VERSION 5.8 ;
BUSBITCHARS "[]" ;
DIVIDERCHAR "/" ;
UNITS
    DATABASE MICRONS 1000 ;
END UNITS

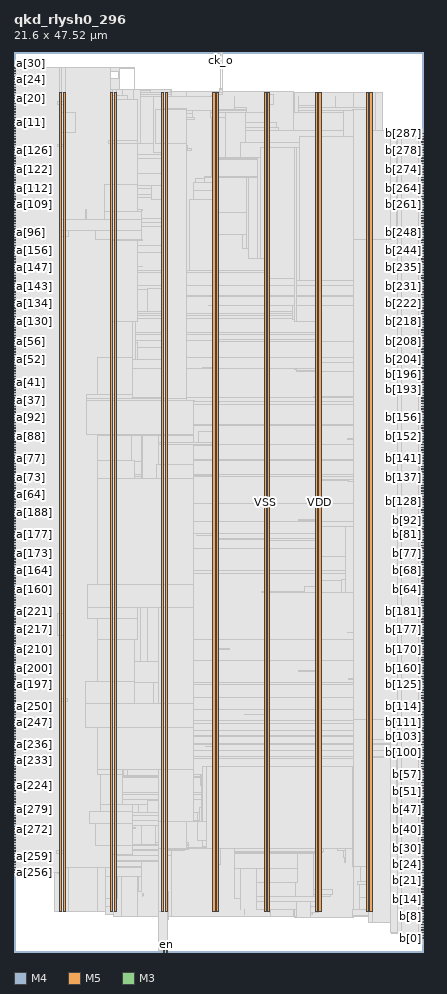
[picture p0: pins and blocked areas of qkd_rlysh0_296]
MACRO qkd_rlysh0_296
  FOREIGN qkd_rlysh0_296 0 0 ;
  CLASS BLOCK ;
  SIZE 21.6 BY 47.52 ;
  PIN a[0]
    DIRECTION INPUT ;
    USE SIGNAL ;
    PORT
      LAYER M4 ;
        RECT  0 42.192 0.084 42.216 ;
    END
  END a[0]
  PIN a[100]
    DIRECTION INPUT ;
    USE SIGNAL ;
    PORT
      LAYER M4 ;
        RECT  0 38.16 0.084 38.184 ;
    END
  END a[100]
  PIN a[101]
    DIRECTION INPUT ;
    USE SIGNAL ;
    PORT
      LAYER M4 ;
        RECT  0 38.304 0.084 38.328 ;
    END
  END a[101]
  PIN a[102]
    DIRECTION INPUT ;
    USE SIGNAL ;
    PORT
      LAYER M4 ;
        RECT  0 38.448 0.084 38.472 ;
    END
  END a[102]
  PIN a[103]
    DIRECTION INPUT ;
    USE SIGNAL ;
    PORT
      LAYER M4 ;
        RECT  0 38.592 0.084 38.616 ;
    END
  END a[103]
  PIN a[104]
    DIRECTION INPUT ;
    USE SIGNAL ;
    PORT
      LAYER M4 ;
        RECT  0 38.736 0.084 38.76 ;
    END
  END a[104]
  PIN a[105]
    DIRECTION INPUT ;
    USE SIGNAL ;
    PORT
      LAYER M4 ;
        RECT  0 38.88 0.084 38.904 ;
    END
  END a[105]
  PIN a[106]
    DIRECTION INPUT ;
    USE SIGNAL ;
    PORT
      LAYER M4 ;
        RECT  0 39.024 0.084 39.048 ;
    END
  END a[106]
  PIN a[107]
    DIRECTION INPUT ;
    USE SIGNAL ;
    PORT
      LAYER M4 ;
        RECT  0 39.168 0.084 39.192 ;
    END
  END a[107]
  PIN a[108]
    DIRECTION INPUT ;
    USE SIGNAL ;
    PORT
      LAYER M4 ;
        RECT  0 39.312 0.084 39.336 ;
    END
  END a[108]
  PIN a[109]
    DIRECTION INPUT ;
    USE SIGNAL ;
    PORT
      LAYER M4 ;
        RECT  0 39.456 0.084 39.48 ;
    END
  END a[109]
  PIN a[10]
    DIRECTION INPUT ;
    USE SIGNAL ;
    PORT
      LAYER M4 ;
        RECT  0 43.632 0.084 43.656 ;
    END
  END a[10]
  PIN a[110]
    DIRECTION INPUT ;
    USE SIGNAL ;
    PORT
      LAYER M4 ;
        RECT  0 39.6 0.084 39.624 ;
    END
  END a[110]
  PIN a[111]
    DIRECTION INPUT ;
    USE SIGNAL ;
    PORT
      LAYER M4 ;
        RECT  0 39.744 0.084 39.768 ;
    END
  END a[111]
  PIN a[112]
    DIRECTION INPUT ;
    USE SIGNAL ;
    PORT
      LAYER M4 ;
        RECT  0 39.888 0.084 39.912 ;
    END
  END a[112]
  PIN a[113]
    DIRECTION INPUT ;
    USE SIGNAL ;
    PORT
      LAYER M4 ;
        RECT  0 40.032 0.084 40.056 ;
    END
  END a[113]
  PIN a[114]
    DIRECTION INPUT ;
    USE SIGNAL ;
    PORT
      LAYER M4 ;
        RECT  0 40.176 0.084 40.2 ;
    END
  END a[114]
  PIN a[115]
    DIRECTION INPUT ;
    USE SIGNAL ;
    PORT
      LAYER M4 ;
        RECT  0 40.32 0.084 40.344 ;
    END
  END a[115]
  PIN a[116]
    DIRECTION INPUT ;
    USE SIGNAL ;
    PORT
      LAYER M4 ;
        RECT  0 40.464 0.084 40.488 ;
    END
  END a[116]
  PIN a[117]
    DIRECTION INPUT ;
    USE SIGNAL ;
    PORT
      LAYER M4 ;
        RECT  0 40.608 0.084 40.632 ;
    END
  END a[117]
  PIN a[118]
    DIRECTION INPUT ;
    USE SIGNAL ;
    PORT
      LAYER M4 ;
        RECT  0 40.752 0.084 40.776 ;
    END
  END a[118]
  PIN a[119]
    DIRECTION INPUT ;
    USE SIGNAL ;
    PORT
      LAYER M4 ;
        RECT  0 40.896 0.084 40.92 ;
    END
  END a[119]
  PIN a[11]
    DIRECTION INPUT ;
    USE SIGNAL ;
    PORT
      LAYER M4 ;
        RECT  0 43.776 0.084 43.8 ;
    END
  END a[11]
  PIN a[120]
    DIRECTION INPUT ;
    USE SIGNAL ;
    PORT
      LAYER M4 ;
        RECT  0 41.04 0.084 41.064 ;
    END
  END a[120]
  PIN a[121]
    DIRECTION INPUT ;
    USE SIGNAL ;
    PORT
      LAYER M4 ;
        RECT  0 41.184 0.084 41.208 ;
    END
  END a[121]
  PIN a[122]
    DIRECTION INPUT ;
    USE SIGNAL ;
    PORT
      LAYER M4 ;
        RECT  0 41.328 0.084 41.352 ;
    END
  END a[122]
  PIN a[123]
    DIRECTION INPUT ;
    USE SIGNAL ;
    PORT
      LAYER M4 ;
        RECT  0 41.472 0.084 41.496 ;
    END
  END a[123]
  PIN a[124]
    DIRECTION INPUT ;
    USE SIGNAL ;
    PORT
      LAYER M4 ;
        RECT  0 41.616 0.084 41.64 ;
    END
  END a[124]
  PIN a[125]
    DIRECTION INPUT ;
    USE SIGNAL ;
    PORT
      LAYER M4 ;
        RECT  0 41.76 0.084 41.784 ;
    END
  END a[125]
  PIN a[126]
    DIRECTION INPUT ;
    USE SIGNAL ;
    PORT
      LAYER M4 ;
        RECT  0 41.904 0.084 41.928 ;
    END
  END a[126]
  PIN a[127]
    DIRECTION INPUT ;
    USE SIGNAL ;
    PORT
      LAYER M4 ;
        RECT  0 42.048 0.084 42.072 ;
    END
  END a[127]
  PIN a[128]
    DIRECTION INPUT ;
    USE SIGNAL ;
    PORT
      LAYER M4 ;
        RECT  0 32.976 0.084 33 ;
    END
  END a[128]
  PIN a[129]
    DIRECTION INPUT ;
    USE SIGNAL ;
    PORT
      LAYER M4 ;
        RECT  0 33.12 0.084 33.144 ;
    END
  END a[129]
  PIN a[12]
    DIRECTION INPUT ;
    USE SIGNAL ;
    PORT
      LAYER M4 ;
        RECT  0 43.92 0.084 43.944 ;
    END
  END a[12]
  PIN a[130]
    DIRECTION INPUT ;
    USE SIGNAL ;
    PORT
      LAYER M4 ;
        RECT  0 33.264 0.084 33.288 ;
    END
  END a[130]
  PIN a[131]
    DIRECTION INPUT ;
    USE SIGNAL ;
    PORT
      LAYER M4 ;
        RECT  0 33.408 0.084 33.432 ;
    END
  END a[131]
  PIN a[132]
    DIRECTION INPUT ;
    USE SIGNAL ;
    PORT
      LAYER M4 ;
        RECT  0 33.552 0.084 33.576 ;
    END
  END a[132]
  PIN a[133]
    DIRECTION INPUT ;
    USE SIGNAL ;
    PORT
      LAYER M4 ;
        RECT  0 33.696 0.084 33.72 ;
    END
  END a[133]
  PIN a[134]
    DIRECTION INPUT ;
    USE SIGNAL ;
    PORT
      LAYER M4 ;
        RECT  0 33.84 0.084 33.864 ;
    END
  END a[134]
  PIN a[135]
    DIRECTION INPUT ;
    USE SIGNAL ;
    PORT
      LAYER M4 ;
        RECT  0 33.984 0.084 34.008 ;
    END
  END a[135]
  PIN a[136]
    DIRECTION INPUT ;
    USE SIGNAL ;
    PORT
      LAYER M4 ;
        RECT  0 34.128 0.084 34.152 ;
    END
  END a[136]
  PIN a[137]
    DIRECTION INPUT ;
    USE SIGNAL ;
    PORT
      LAYER M4 ;
        RECT  0 34.272 0.084 34.296 ;
    END
  END a[137]
  PIN a[138]
    DIRECTION INPUT ;
    USE SIGNAL ;
    PORT
      LAYER M4 ;
        RECT  0 34.416 0.084 34.44 ;
    END
  END a[138]
  PIN a[139]
    DIRECTION INPUT ;
    USE SIGNAL ;
    PORT
      LAYER M4 ;
        RECT  0 34.56 0.084 34.584 ;
    END
  END a[139]
  PIN a[13]
    DIRECTION INPUT ;
    USE SIGNAL ;
    PORT
      LAYER M4 ;
        RECT  0 44.064 0.084 44.088 ;
    END
  END a[13]
  PIN a[140]
    DIRECTION INPUT ;
    USE SIGNAL ;
    PORT
      LAYER M4 ;
        RECT  0 34.704 0.084 34.728 ;
    END
  END a[140]
  PIN a[141]
    DIRECTION INPUT ;
    USE SIGNAL ;
    PORT
      LAYER M4 ;
        RECT  0 34.848 0.084 34.872 ;
    END
  END a[141]
  PIN a[142]
    DIRECTION INPUT ;
    USE SIGNAL ;
    PORT
      LAYER M4 ;
        RECT  0 34.992 0.084 35.016 ;
    END
  END a[142]
  PIN a[143]
    DIRECTION INPUT ;
    USE SIGNAL ;
    PORT
      LAYER M4 ;
        RECT  0 35.136 0.084 35.16 ;
    END
  END a[143]
  PIN a[144]
    DIRECTION INPUT ;
    USE SIGNAL ;
    PORT
      LAYER M4 ;
        RECT  0 35.28 0.084 35.304 ;
    END
  END a[144]
  PIN a[145]
    DIRECTION INPUT ;
    USE SIGNAL ;
    PORT
      LAYER M4 ;
        RECT  0 35.424 0.084 35.448 ;
    END
  END a[145]
  PIN a[146]
    DIRECTION INPUT ;
    USE SIGNAL ;
    PORT
      LAYER M4 ;
        RECT  0 35.568 0.084 35.592 ;
    END
  END a[146]
  PIN a[147]
    DIRECTION INPUT ;
    USE SIGNAL ;
    PORT
      LAYER M4 ;
        RECT  0 35.712 0.084 35.736 ;
    END
  END a[147]
  PIN a[148]
    DIRECTION INPUT ;
    USE SIGNAL ;
    PORT
      LAYER M4 ;
        RECT  0 35.856 0.084 35.88 ;
    END
  END a[148]
  PIN a[149]
    DIRECTION INPUT ;
    USE SIGNAL ;
    PORT
      LAYER M4 ;
        RECT  0 36 0.084 36.024 ;
    END
  END a[149]
  PIN a[14]
    DIRECTION INPUT ;
    USE SIGNAL ;
    PORT
      LAYER M4 ;
        RECT  0 44.208 0.084 44.232 ;
    END
  END a[14]
  PIN a[150]
    DIRECTION INPUT ;
    USE SIGNAL ;
    PORT
      LAYER M4 ;
        RECT  0 36.144 0.084 36.168 ;
    END
  END a[150]
  PIN a[151]
    DIRECTION INPUT ;
    USE SIGNAL ;
    PORT
      LAYER M4 ;
        RECT  0 36.288 0.084 36.312 ;
    END
  END a[151]
  PIN a[152]
    DIRECTION INPUT ;
    USE SIGNAL ;
    PORT
      LAYER M4 ;
        RECT  0 36.432 0.084 36.456 ;
    END
  END a[152]
  PIN a[153]
    DIRECTION INPUT ;
    USE SIGNAL ;
    PORT
      LAYER M4 ;
        RECT  0 36.576 0.084 36.6 ;
    END
  END a[153]
  PIN a[154]
    DIRECTION INPUT ;
    USE SIGNAL ;
    PORT
      LAYER M4 ;
        RECT  0 36.72 0.084 36.744 ;
    END
  END a[154]
  PIN a[155]
    DIRECTION INPUT ;
    USE SIGNAL ;
    PORT
      LAYER M4 ;
        RECT  0 36.864 0.084 36.888 ;
    END
  END a[155]
  PIN a[156]
    DIRECTION INPUT ;
    USE SIGNAL ;
    PORT
      LAYER M4 ;
        RECT  0 37.008 0.084 37.032 ;
    END
  END a[156]
  PIN a[157]
    DIRECTION INPUT ;
    USE SIGNAL ;
    PORT
      LAYER M4 ;
        RECT  0 37.152 0.084 37.176 ;
    END
  END a[157]
  PIN a[158]
    DIRECTION INPUT ;
    USE SIGNAL ;
    PORT
      LAYER M4 ;
        RECT  0 37.296 0.084 37.32 ;
    END
  END a[158]
  PIN a[159]
    DIRECTION INPUT ;
    USE SIGNAL ;
    PORT
      LAYER M4 ;
        RECT  0 37.44 0.084 37.464 ;
    END
  END a[159]
  PIN a[15]
    DIRECTION INPUT ;
    USE SIGNAL ;
    PORT
      LAYER M4 ;
        RECT  0 44.352 0.084 44.376 ;
    END
  END a[15]
  PIN a[160]
    DIRECTION INPUT ;
    USE SIGNAL ;
    PORT
      LAYER M4 ;
        RECT  0 19.152 0.084 19.176 ;
    END
  END a[160]
  PIN a[161]
    DIRECTION INPUT ;
    USE SIGNAL ;
    PORT
      LAYER M4 ;
        RECT  0 19.296 0.084 19.32 ;
    END
  END a[161]
  PIN a[162]
    DIRECTION INPUT ;
    USE SIGNAL ;
    PORT
      LAYER M4 ;
        RECT  0 19.44 0.084 19.464 ;
    END
  END a[162]
  PIN a[163]
    DIRECTION INPUT ;
    USE SIGNAL ;
    PORT
      LAYER M4 ;
        RECT  0 19.584 0.084 19.608 ;
    END
  END a[163]
  PIN a[164]
    DIRECTION INPUT ;
    USE SIGNAL ;
    PORT
      LAYER M4 ;
        RECT  0 19.728 0.084 19.752 ;
    END
  END a[164]
  PIN a[165]
    DIRECTION INPUT ;
    USE SIGNAL ;
    PORT
      LAYER M4 ;
        RECT  0 19.872 0.084 19.896 ;
    END
  END a[165]
  PIN a[166]
    DIRECTION INPUT ;
    USE SIGNAL ;
    PORT
      LAYER M4 ;
        RECT  0 20.016 0.084 20.04 ;
    END
  END a[166]
  PIN a[167]
    DIRECTION INPUT ;
    USE SIGNAL ;
    PORT
      LAYER M4 ;
        RECT  0 20.16 0.084 20.184 ;
    END
  END a[167]
  PIN a[168]
    DIRECTION INPUT ;
    USE SIGNAL ;
    PORT
      LAYER M4 ;
        RECT  0 20.304 0.084 20.328 ;
    END
  END a[168]
  PIN a[169]
    DIRECTION INPUT ;
    USE SIGNAL ;
    PORT
      LAYER M4 ;
        RECT  0 20.448 0.084 20.472 ;
    END
  END a[169]
  PIN a[16]
    DIRECTION INPUT ;
    USE SIGNAL ;
    PORT
      LAYER M4 ;
        RECT  0 44.496 0.084 44.52 ;
    END
  END a[16]
  PIN a[170]
    DIRECTION INPUT ;
    USE SIGNAL ;
    PORT
      LAYER M4 ;
        RECT  0 20.592 0.084 20.616 ;
    END
  END a[170]
  PIN a[171]
    DIRECTION INPUT ;
    USE SIGNAL ;
    PORT
      LAYER M4 ;
        RECT  0 20.736 0.084 20.76 ;
    END
  END a[171]
  PIN a[172]
    DIRECTION INPUT ;
    USE SIGNAL ;
    PORT
      LAYER M4 ;
        RECT  0 20.88 0.084 20.904 ;
    END
  END a[172]
  PIN a[173]
    DIRECTION INPUT ;
    USE SIGNAL ;
    PORT
      LAYER M4 ;
        RECT  0 21.024 0.084 21.048 ;
    END
  END a[173]
  PIN a[174]
    DIRECTION INPUT ;
    USE SIGNAL ;
    PORT
      LAYER M4 ;
        RECT  0 21.168 0.084 21.192 ;
    END
  END a[174]
  PIN a[175]
    DIRECTION INPUT ;
    USE SIGNAL ;
    PORT
      LAYER M4 ;
        RECT  0 21.312 0.084 21.336 ;
    END
  END a[175]
  PIN a[176]
    DIRECTION INPUT ;
    USE SIGNAL ;
    PORT
      LAYER M4 ;
        RECT  0 21.456 0.084 21.48 ;
    END
  END a[176]
  PIN a[177]
    DIRECTION INPUT ;
    USE SIGNAL ;
    PORT
      LAYER M4 ;
        RECT  0 21.6 0.084 21.624 ;
    END
  END a[177]
  PIN a[178]
    DIRECTION INPUT ;
    USE SIGNAL ;
    PORT
      LAYER M4 ;
        RECT  0 21.744 0.084 21.768 ;
    END
  END a[178]
  PIN a[179]
    DIRECTION INPUT ;
    USE SIGNAL ;
    PORT
      LAYER M4 ;
        RECT  0 21.888 0.084 21.912 ;
    END
  END a[179]
  PIN a[17]
    DIRECTION INPUT ;
    USE SIGNAL ;
    PORT
      LAYER M4 ;
        RECT  0 44.64 0.084 44.664 ;
    END
  END a[17]
  PIN a[180]
    DIRECTION INPUT ;
    USE SIGNAL ;
    PORT
      LAYER M4 ;
        RECT  0 22.032 0.084 22.056 ;
    END
  END a[180]
  PIN a[181]
    DIRECTION INPUT ;
    USE SIGNAL ;
    PORT
      LAYER M4 ;
        RECT  0 22.176 0.084 22.2 ;
    END
  END a[181]
  PIN a[182]
    DIRECTION INPUT ;
    USE SIGNAL ;
    PORT
      LAYER M4 ;
        RECT  0 22.32 0.084 22.344 ;
    END
  END a[182]
  PIN a[183]
    DIRECTION INPUT ;
    USE SIGNAL ;
    PORT
      LAYER M4 ;
        RECT  0 22.464 0.084 22.488 ;
    END
  END a[183]
  PIN a[184]
    DIRECTION INPUT ;
    USE SIGNAL ;
    PORT
      LAYER M4 ;
        RECT  0 22.608 0.084 22.632 ;
    END
  END a[184]
  PIN a[185]
    DIRECTION INPUT ;
    USE SIGNAL ;
    PORT
      LAYER M4 ;
        RECT  0 22.752 0.084 22.776 ;
    END
  END a[185]
  PIN a[186]
    DIRECTION INPUT ;
    USE SIGNAL ;
    PORT
      LAYER M4 ;
        RECT  0 22.896 0.084 22.92 ;
    END
  END a[186]
  PIN a[187]
    DIRECTION INPUT ;
    USE SIGNAL ;
    PORT
      LAYER M4 ;
        RECT  0 23.04 0.084 23.064 ;
    END
  END a[187]
  PIN a[188]
    DIRECTION INPUT ;
    USE SIGNAL ;
    PORT
      LAYER M4 ;
        RECT  0 23.184 0.084 23.208 ;
    END
  END a[188]
  PIN a[189]
    DIRECTION INPUT ;
    USE SIGNAL ;
    PORT
      LAYER M4 ;
        RECT  0 23.328 0.084 23.352 ;
    END
  END a[189]
  PIN a[18]
    DIRECTION INPUT ;
    USE SIGNAL ;
    PORT
      LAYER M4 ;
        RECT  0 44.784 0.084 44.808 ;
    END
  END a[18]
  PIN a[190]
    DIRECTION INPUT ;
    USE SIGNAL ;
    PORT
      LAYER M4 ;
        RECT  0 23.472 0.084 23.496 ;
    END
  END a[190]
  PIN a[191]
    DIRECTION INPUT ;
    USE SIGNAL ;
    PORT
      LAYER M4 ;
        RECT  0 23.616 0.084 23.64 ;
    END
  END a[191]
  PIN a[192]
    DIRECTION INPUT ;
    USE SIGNAL ;
    PORT
      LAYER M4 ;
        RECT  0 13.392 0.084 13.416 ;
    END
  END a[192]
  PIN a[193]
    DIRECTION INPUT ;
    USE SIGNAL ;
    PORT
      LAYER M4 ;
        RECT  0 13.536 0.084 13.56 ;
    END
  END a[193]
  PIN a[194]
    DIRECTION INPUT ;
    USE SIGNAL ;
    PORT
      LAYER M4 ;
        RECT  0 13.68 0.084 13.704 ;
    END
  END a[194]
  PIN a[195]
    DIRECTION INPUT ;
    USE SIGNAL ;
    PORT
      LAYER M4 ;
        RECT  0 13.824 0.084 13.848 ;
    END
  END a[195]
  PIN a[196]
    DIRECTION INPUT ;
    USE SIGNAL ;
    PORT
      LAYER M4 ;
        RECT  0 13.968 0.084 13.992 ;
    END
  END a[196]
  PIN a[197]
    DIRECTION INPUT ;
    USE SIGNAL ;
    PORT
      LAYER M4 ;
        RECT  0 14.112 0.084 14.136 ;
    END
  END a[197]
  PIN a[198]
    DIRECTION INPUT ;
    USE SIGNAL ;
    PORT
      LAYER M4 ;
        RECT  0 14.256 0.084 14.28 ;
    END
  END a[198]
  PIN a[199]
    DIRECTION INPUT ;
    USE SIGNAL ;
    PORT
      LAYER M4 ;
        RECT  0 14.4 0.084 14.424 ;
    END
  END a[199]
  PIN a[19]
    DIRECTION INPUT ;
    USE SIGNAL ;
    PORT
      LAYER M4 ;
        RECT  0 44.928 0.084 44.952 ;
    END
  END a[19]
  PIN a[1]
    DIRECTION INPUT ;
    USE SIGNAL ;
    PORT
      LAYER M4 ;
        RECT  0 42.336 0.084 42.36 ;
    END
  END a[1]
  PIN a[200]
    DIRECTION INPUT ;
    USE SIGNAL ;
    PORT
      LAYER M4 ;
        RECT  0 14.544 0.084 14.568 ;
    END
  END a[200]
  PIN a[201]
    DIRECTION INPUT ;
    USE SIGNAL ;
    PORT
      LAYER M4 ;
        RECT  0 14.688 0.084 14.712 ;
    END
  END a[201]
  PIN a[202]
    DIRECTION INPUT ;
    USE SIGNAL ;
    PORT
      LAYER M4 ;
        RECT  0 14.832 0.084 14.856 ;
    END
  END a[202]
  PIN a[203]
    DIRECTION INPUT ;
    USE SIGNAL ;
    PORT
      LAYER M4 ;
        RECT  0 14.976 0.084 15 ;
    END
  END a[203]
  PIN a[204]
    DIRECTION INPUT ;
    USE SIGNAL ;
    PORT
      LAYER M4 ;
        RECT  0 15.12 0.084 15.144 ;
    END
  END a[204]
  PIN a[205]
    DIRECTION INPUT ;
    USE SIGNAL ;
    PORT
      LAYER M4 ;
        RECT  0 15.264 0.084 15.288 ;
    END
  END a[205]
  PIN a[206]
    DIRECTION INPUT ;
    USE SIGNAL ;
    PORT
      LAYER M4 ;
        RECT  0 15.408 0.084 15.432 ;
    END
  END a[206]
  PIN a[207]
    DIRECTION INPUT ;
    USE SIGNAL ;
    PORT
      LAYER M4 ;
        RECT  0 15.552 0.084 15.576 ;
    END
  END a[207]
  PIN a[208]
    DIRECTION INPUT ;
    USE SIGNAL ;
    PORT
      LAYER M4 ;
        RECT  0 15.696 0.084 15.72 ;
    END
  END a[208]
  PIN a[209]
    DIRECTION INPUT ;
    USE SIGNAL ;
    PORT
      LAYER M4 ;
        RECT  0 15.84 0.084 15.864 ;
    END
  END a[209]
  PIN a[20]
    DIRECTION INPUT ;
    USE SIGNAL ;
    PORT
      LAYER M4 ;
        RECT  0 45.072 0.084 45.096 ;
    END
  END a[20]
  PIN a[210]
    DIRECTION INPUT ;
    USE SIGNAL ;
    PORT
      LAYER M4 ;
        RECT  0 15.984 0.084 16.008 ;
    END
  END a[210]
  PIN a[211]
    DIRECTION INPUT ;
    USE SIGNAL ;
    PORT
      LAYER M4 ;
        RECT  0 16.128 0.084 16.152 ;
    END
  END a[211]
  PIN a[212]
    DIRECTION INPUT ;
    USE SIGNAL ;
    PORT
      LAYER M4 ;
        RECT  0 16.272 0.084 16.296 ;
    END
  END a[212]
  PIN a[213]
    DIRECTION INPUT ;
    USE SIGNAL ;
    PORT
      LAYER M4 ;
        RECT  0 16.416 0.084 16.44 ;
    END
  END a[213]
  PIN a[214]
    DIRECTION INPUT ;
    USE SIGNAL ;
    PORT
      LAYER M4 ;
        RECT  0 16.56 0.084 16.584 ;
    END
  END a[214]
  PIN a[215]
    DIRECTION INPUT ;
    USE SIGNAL ;
    PORT
      LAYER M4 ;
        RECT  0 16.704 0.084 16.728 ;
    END
  END a[215]
  PIN a[216]
    DIRECTION INPUT ;
    USE SIGNAL ;
    PORT
      LAYER M4 ;
        RECT  0 16.848 0.084 16.872 ;
    END
  END a[216]
  PIN a[217]
    DIRECTION INPUT ;
    USE SIGNAL ;
    PORT
      LAYER M4 ;
        RECT  0 16.992 0.084 17.016 ;
    END
  END a[217]
  PIN a[218]
    DIRECTION INPUT ;
    USE SIGNAL ;
    PORT
      LAYER M4 ;
        RECT  0 17.136 0.084 17.16 ;
    END
  END a[218]
  PIN a[219]
    DIRECTION INPUT ;
    USE SIGNAL ;
    PORT
      LAYER M4 ;
        RECT  0 17.28 0.084 17.304 ;
    END
  END a[219]
  PIN a[21]
    DIRECTION INPUT ;
    USE SIGNAL ;
    PORT
      LAYER M4 ;
        RECT  0 45.216 0.084 45.24 ;
    END
  END a[21]
  PIN a[220]
    DIRECTION INPUT ;
    USE SIGNAL ;
    PORT
      LAYER M4 ;
        RECT  0 17.424 0.084 17.448 ;
    END
  END a[220]
  PIN a[221]
    DIRECTION INPUT ;
    USE SIGNAL ;
    PORT
      LAYER M4 ;
        RECT  0 17.568 0.084 17.592 ;
    END
  END a[221]
  PIN a[222]
    DIRECTION INPUT ;
    USE SIGNAL ;
    PORT
      LAYER M4 ;
        RECT  0 17.712 0.084 17.736 ;
    END
  END a[222]
  PIN a[223]
    DIRECTION INPUT ;
    USE SIGNAL ;
    PORT
      LAYER M4 ;
        RECT  0 17.856 0.084 17.88 ;
    END
  END a[223]
  PIN a[224]
    DIRECTION INPUT ;
    USE SIGNAL ;
    PORT
      LAYER M4 ;
        RECT  0 8.784 0.084 8.808 ;
    END
  END a[224]
  PIN a[225]
    DIRECTION INPUT ;
    USE SIGNAL ;
    PORT
      LAYER M4 ;
        RECT  0 8.928 0.084 8.952 ;
    END
  END a[225]
  PIN a[226]
    DIRECTION INPUT ;
    USE SIGNAL ;
    PORT
      LAYER M4 ;
        RECT  0 9.072 0.084 9.096 ;
    END
  END a[226]
  PIN a[227]
    DIRECTION INPUT ;
    USE SIGNAL ;
    PORT
      LAYER M4 ;
        RECT  0 9.216 0.084 9.24 ;
    END
  END a[227]
  PIN a[228]
    DIRECTION INPUT ;
    USE SIGNAL ;
    PORT
      LAYER M4 ;
        RECT  0 9.36 0.084 9.384 ;
    END
  END a[228]
  PIN a[229]
    DIRECTION INPUT ;
    USE SIGNAL ;
    PORT
      LAYER M4 ;
        RECT  0 9.504 0.084 9.528 ;
    END
  END a[229]
  PIN a[22]
    DIRECTION INPUT ;
    USE SIGNAL ;
    PORT
      LAYER M4 ;
        RECT  0 45.36 0.084 45.384 ;
    END
  END a[22]
  PIN a[230]
    DIRECTION INPUT ;
    USE SIGNAL ;
    PORT
      LAYER M4 ;
        RECT  0 9.648 0.084 9.672 ;
    END
  END a[230]
  PIN a[231]
    DIRECTION INPUT ;
    USE SIGNAL ;
    PORT
      LAYER M4 ;
        RECT  0 9.792 0.084 9.816 ;
    END
  END a[231]
  PIN a[232]
    DIRECTION INPUT ;
    USE SIGNAL ;
    PORT
      LAYER M4 ;
        RECT  0 9.936 0.084 9.96 ;
    END
  END a[232]
  PIN a[233]
    DIRECTION INPUT ;
    USE SIGNAL ;
    PORT
      LAYER M4 ;
        RECT  0 10.08 0.084 10.104 ;
    END
  END a[233]
  PIN a[234]
    DIRECTION INPUT ;
    USE SIGNAL ;
    PORT
      LAYER M4 ;
        RECT  0 10.224 0.084 10.248 ;
    END
  END a[234]
  PIN a[235]
    DIRECTION INPUT ;
    USE SIGNAL ;
    PORT
      LAYER M4 ;
        RECT  0 10.368 0.084 10.392 ;
    END
  END a[235]
  PIN a[236]
    DIRECTION INPUT ;
    USE SIGNAL ;
    PORT
      LAYER M4 ;
        RECT  0 10.512 0.084 10.536 ;
    END
  END a[236]
  PIN a[237]
    DIRECTION INPUT ;
    USE SIGNAL ;
    PORT
      LAYER M4 ;
        RECT  0 10.656 0.084 10.68 ;
    END
  END a[237]
  PIN a[238]
    DIRECTION INPUT ;
    USE SIGNAL ;
    PORT
      LAYER M4 ;
        RECT  0 10.8 0.084 10.824 ;
    END
  END a[238]
  PIN a[239]
    DIRECTION INPUT ;
    USE SIGNAL ;
    PORT
      LAYER M4 ;
        RECT  0 10.944 0.084 10.968 ;
    END
  END a[239]
  PIN a[23]
    DIRECTION INPUT ;
    USE SIGNAL ;
    PORT
      LAYER M4 ;
        RECT  0 45.504 0.084 45.528 ;
    END
  END a[23]
  PIN a[240]
    DIRECTION INPUT ;
    USE SIGNAL ;
    PORT
      LAYER M4 ;
        RECT  0 11.088 0.084 11.112 ;
    END
  END a[240]
  PIN a[241]
    DIRECTION INPUT ;
    USE SIGNAL ;
    PORT
      LAYER M4 ;
        RECT  0 11.232 0.084 11.256 ;
    END
  END a[241]
  PIN a[242]
    DIRECTION INPUT ;
    USE SIGNAL ;
    PORT
      LAYER M4 ;
        RECT  0 11.376 0.084 11.4 ;
    END
  END a[242]
  PIN a[243]
    DIRECTION INPUT ;
    USE SIGNAL ;
    PORT
      LAYER M4 ;
        RECT  0 11.52 0.084 11.544 ;
    END
  END a[243]
  PIN a[244]
    DIRECTION INPUT ;
    USE SIGNAL ;
    PORT
      LAYER M4 ;
        RECT  0 11.664 0.084 11.688 ;
    END
  END a[244]
  PIN a[245]
    DIRECTION INPUT ;
    USE SIGNAL ;
    PORT
      LAYER M4 ;
        RECT  0 11.808 0.084 11.832 ;
    END
  END a[245]
  PIN a[246]
    DIRECTION INPUT ;
    USE SIGNAL ;
    PORT
      LAYER M4 ;
        RECT  0 11.952 0.084 11.976 ;
    END
  END a[246]
  PIN a[247]
    DIRECTION INPUT ;
    USE SIGNAL ;
    PORT
      LAYER M4 ;
        RECT  0 12.096 0.084 12.12 ;
    END
  END a[247]
  PIN a[248]
    DIRECTION INPUT ;
    USE SIGNAL ;
    PORT
      LAYER M4 ;
        RECT  0 12.24 0.084 12.264 ;
    END
  END a[248]
  PIN a[249]
    DIRECTION INPUT ;
    USE SIGNAL ;
    PORT
      LAYER M4 ;
        RECT  0 12.384 0.084 12.408 ;
    END
  END a[249]
  PIN a[24]
    DIRECTION INPUT ;
    USE SIGNAL ;
    PORT
      LAYER M4 ;
        RECT  0 45.648 0.084 45.672 ;
    END
  END a[24]
  PIN a[250]
    DIRECTION INPUT ;
    USE SIGNAL ;
    PORT
      LAYER M4 ;
        RECT  0 12.528 0.084 12.552 ;
    END
  END a[250]
  PIN a[251]
    DIRECTION INPUT ;
    USE SIGNAL ;
    PORT
      LAYER M4 ;
        RECT  0 12.672 0.084 12.696 ;
    END
  END a[251]
  PIN a[252]
    DIRECTION INPUT ;
    USE SIGNAL ;
    PORT
      LAYER M4 ;
        RECT  0 12.816 0.084 12.84 ;
    END
  END a[252]
  PIN a[253]
    DIRECTION INPUT ;
    USE SIGNAL ;
    PORT
      LAYER M4 ;
        RECT  0 12.96 0.084 12.984 ;
    END
  END a[253]
  PIN a[254]
    DIRECTION INPUT ;
    USE SIGNAL ;
    PORT
      LAYER M4 ;
        RECT  0 13.104 0.084 13.128 ;
    END
  END a[254]
  PIN a[255]
    DIRECTION INPUT ;
    USE SIGNAL ;
    PORT
      LAYER M4 ;
        RECT  0 13.248 0.084 13.272 ;
    END
  END a[255]
  PIN a[256]
    DIRECTION INPUT ;
    USE SIGNAL ;
    PORT
      LAYER M4 ;
        RECT  0 4.176 0.084 4.2 ;
    END
  END a[256]
  PIN a[257]
    DIRECTION INPUT ;
    USE SIGNAL ;
    PORT
      LAYER M4 ;
        RECT  0 4.32 0.084 4.344 ;
    END
  END a[257]
  PIN a[258]
    DIRECTION INPUT ;
    USE SIGNAL ;
    PORT
      LAYER M4 ;
        RECT  0 4.464 0.084 4.488 ;
    END
  END a[258]
  PIN a[259]
    DIRECTION INPUT ;
    USE SIGNAL ;
    PORT
      LAYER M4 ;
        RECT  0 4.608 0.084 4.632 ;
    END
  END a[259]
  PIN a[25]
    DIRECTION INPUT ;
    USE SIGNAL ;
    PORT
      LAYER M4 ;
        RECT  0 45.792 0.084 45.816 ;
    END
  END a[25]
  PIN a[260]
    DIRECTION INPUT ;
    USE SIGNAL ;
    PORT
      LAYER M4 ;
        RECT  0 4.752 0.084 4.776 ;
    END
  END a[260]
  PIN a[261]
    DIRECTION INPUT ;
    USE SIGNAL ;
    PORT
      LAYER M4 ;
        RECT  0 4.896 0.084 4.92 ;
    END
  END a[261]
  PIN a[262]
    DIRECTION INPUT ;
    USE SIGNAL ;
    PORT
      LAYER M4 ;
        RECT  0 5.04 0.084 5.064 ;
    END
  END a[262]
  PIN a[263]
    DIRECTION INPUT ;
    USE SIGNAL ;
    PORT
      LAYER M4 ;
        RECT  0 5.184 0.084 5.208 ;
    END
  END a[263]
  PIN a[264]
    DIRECTION INPUT ;
    USE SIGNAL ;
    PORT
      LAYER M4 ;
        RECT  0 5.328 0.084 5.352 ;
    END
  END a[264]
  PIN a[265]
    DIRECTION INPUT ;
    USE SIGNAL ;
    PORT
      LAYER M4 ;
        RECT  0 5.472 0.084 5.496 ;
    END
  END a[265]
  PIN a[266]
    DIRECTION INPUT ;
    USE SIGNAL ;
    PORT
      LAYER M4 ;
        RECT  0 5.616 0.084 5.64 ;
    END
  END a[266]
  PIN a[267]
    DIRECTION INPUT ;
    USE SIGNAL ;
    PORT
      LAYER M4 ;
        RECT  0 5.76 0.084 5.784 ;
    END
  END a[267]
  PIN a[268]
    DIRECTION INPUT ;
    USE SIGNAL ;
    PORT
      LAYER M4 ;
        RECT  0 5.904 0.084 5.928 ;
    END
  END a[268]
  PIN a[269]
    DIRECTION INPUT ;
    USE SIGNAL ;
    PORT
      LAYER M4 ;
        RECT  0 6.048 0.084 6.072 ;
    END
  END a[269]
  PIN a[26]
    DIRECTION INPUT ;
    USE SIGNAL ;
    PORT
      LAYER M4 ;
        RECT  0 45.936 0.084 45.96 ;
    END
  END a[26]
  PIN a[270]
    DIRECTION INPUT ;
    USE SIGNAL ;
    PORT
      LAYER M4 ;
        RECT  0 6.192 0.084 6.216 ;
    END
  END a[270]
  PIN a[271]
    DIRECTION INPUT ;
    USE SIGNAL ;
    PORT
      LAYER M4 ;
        RECT  0 6.336 0.084 6.36 ;
    END
  END a[271]
  PIN a[272]
    DIRECTION INPUT ;
    USE SIGNAL ;
    PORT
      LAYER M4 ;
        RECT  0 6.48 0.084 6.504 ;
    END
  END a[272]
  PIN a[273]
    DIRECTION INPUT ;
    USE SIGNAL ;
    PORT
      LAYER M4 ;
        RECT  0 6.624 0.084 6.648 ;
    END
  END a[273]
  PIN a[274]
    DIRECTION INPUT ;
    USE SIGNAL ;
    PORT
      LAYER M4 ;
        RECT  0 6.768 0.084 6.792 ;
    END
  END a[274]
  PIN a[275]
    DIRECTION INPUT ;
    USE SIGNAL ;
    PORT
      LAYER M4 ;
        RECT  0 6.912 0.084 6.936 ;
    END
  END a[275]
  PIN a[276]
    DIRECTION INPUT ;
    USE SIGNAL ;
    PORT
      LAYER M4 ;
        RECT  0 7.056 0.084 7.08 ;
    END
  END a[276]
  PIN a[277]
    DIRECTION INPUT ;
    USE SIGNAL ;
    PORT
      LAYER M4 ;
        RECT  0 7.2 0.084 7.224 ;
    END
  END a[277]
  PIN a[278]
    DIRECTION INPUT ;
    USE SIGNAL ;
    PORT
      LAYER M4 ;
        RECT  0 7.344 0.084 7.368 ;
    END
  END a[278]
  PIN a[279]
    DIRECTION INPUT ;
    USE SIGNAL ;
    PORT
      LAYER M4 ;
        RECT  0 7.488 0.084 7.512 ;
    END
  END a[279]
  PIN a[27]
    DIRECTION INPUT ;
    USE SIGNAL ;
    PORT
      LAYER M4 ;
        RECT  0 46.08 0.084 46.104 ;
    END
  END a[27]
  PIN a[280]
    DIRECTION INPUT ;
    USE SIGNAL ;
    PORT
      LAYER M4 ;
        RECT  0 7.632 0.084 7.656 ;
    END
  END a[280]
  PIN a[281]
    DIRECTION INPUT ;
    USE SIGNAL ;
    PORT
      LAYER M4 ;
        RECT  0 7.776 0.084 7.8 ;
    END
  END a[281]
  PIN a[282]
    DIRECTION INPUT ;
    USE SIGNAL ;
    PORT
      LAYER M4 ;
        RECT  0 7.92 0.084 7.944 ;
    END
  END a[282]
  PIN a[283]
    DIRECTION INPUT ;
    USE SIGNAL ;
    PORT
      LAYER M4 ;
        RECT  0 8.064 0.084 8.088 ;
    END
  END a[283]
  PIN a[284]
    DIRECTION INPUT ;
    USE SIGNAL ;
    PORT
      LAYER M4 ;
        RECT  0 8.208 0.084 8.232 ;
    END
  END a[284]
  PIN a[285]
    DIRECTION INPUT ;
    USE SIGNAL ;
    PORT
      LAYER M4 ;
        RECT  0 8.352 0.084 8.376 ;
    END
  END a[285]
  PIN a[286]
    DIRECTION INPUT ;
    USE SIGNAL ;
    PORT
      LAYER M4 ;
        RECT  0 8.496 0.084 8.52 ;
    END
  END a[286]
  PIN a[287]
    DIRECTION INPUT ;
    USE SIGNAL ;
    PORT
      LAYER M4 ;
        RECT  0 8.64 0.084 8.664 ;
    END
  END a[287]
  PIN a[288]
    DIRECTION INPUT ;
    USE SIGNAL ;
    PORT
      LAYER M4 ;
        RECT  0 18 0.084 18.024 ;
    END
  END a[288]
  PIN a[289]
    DIRECTION INPUT ;
    USE SIGNAL ;
    PORT
      LAYER M4 ;
        RECT  0 18.144 0.084 18.168 ;
    END
  END a[289]
  PIN a[28]
    DIRECTION INPUT ;
    USE SIGNAL ;
    PORT
      LAYER M4 ;
        RECT  0 46.224 0.084 46.248 ;
    END
  END a[28]
  PIN a[290]
    DIRECTION INPUT ;
    USE SIGNAL ;
    PORT
      LAYER M4 ;
        RECT  0 18.288 0.084 18.312 ;
    END
  END a[290]
  PIN a[291]
    DIRECTION INPUT ;
    USE SIGNAL ;
    PORT
      LAYER M4 ;
        RECT  0 18.432 0.084 18.456 ;
    END
  END a[291]
  PIN a[292]
    DIRECTION INPUT ;
    USE SIGNAL ;
    PORT
      LAYER M4 ;
        RECT  0 18.576 0.084 18.6 ;
    END
  END a[292]
  PIN a[293]
    DIRECTION INPUT ;
    USE SIGNAL ;
    PORT
      LAYER M4 ;
        RECT  0 18.72 0.084 18.744 ;
    END
  END a[293]
  PIN a[294]
    DIRECTION INPUT ;
    USE SIGNAL ;
    PORT
      LAYER M4 ;
        RECT  0 18.864 0.084 18.888 ;
    END
  END a[294]
  PIN a[295]
    DIRECTION INPUT ;
    USE SIGNAL ;
    PORT
      LAYER M4 ;
        RECT  0 19.008 0.084 19.032 ;
    END
  END a[295]
  PIN a[29]
    DIRECTION INPUT ;
    USE SIGNAL ;
    PORT
      LAYER M4 ;
        RECT  0 46.368 0.084 46.392 ;
    END
  END a[29]
  PIN a[2]
    DIRECTION INPUT ;
    USE SIGNAL ;
    PORT
      LAYER M4 ;
        RECT  0 42.48 0.084 42.504 ;
    END
  END a[2]
  PIN a[30]
    DIRECTION INPUT ;
    USE SIGNAL ;
    PORT
      LAYER M4 ;
        RECT  0 46.512 0.084 46.536 ;
    END
  END a[30]
  PIN a[31]
    DIRECTION INPUT ;
    USE SIGNAL ;
    PORT
      LAYER M4 ;
        RECT  0 46.656 0.084 46.68 ;
    END
  END a[31]
  PIN a[32]
    DIRECTION INPUT ;
    USE SIGNAL ;
    PORT
      LAYER M4 ;
        RECT  0 28.368 0.084 28.392 ;
    END
  END a[32]
  PIN a[33]
    DIRECTION INPUT ;
    USE SIGNAL ;
    PORT
      LAYER M4 ;
        RECT  0 28.512 0.084 28.536 ;
    END
  END a[33]
  PIN a[34]
    DIRECTION INPUT ;
    USE SIGNAL ;
    PORT
      LAYER M4 ;
        RECT  0 28.656 0.084 28.68 ;
    END
  END a[34]
  PIN a[35]
    DIRECTION INPUT ;
    USE SIGNAL ;
    PORT
      LAYER M4 ;
        RECT  0 28.8 0.084 28.824 ;
    END
  END a[35]
  PIN a[36]
    DIRECTION INPUT ;
    USE SIGNAL ;
    PORT
      LAYER M4 ;
        RECT  0 28.944 0.084 28.968 ;
    END
  END a[36]
  PIN a[37]
    DIRECTION INPUT ;
    USE SIGNAL ;
    PORT
      LAYER M4 ;
        RECT  0 29.088 0.084 29.112 ;
    END
  END a[37]
  PIN a[38]
    DIRECTION INPUT ;
    USE SIGNAL ;
    PORT
      LAYER M4 ;
        RECT  0 29.232 0.084 29.256 ;
    END
  END a[38]
  PIN a[39]
    DIRECTION INPUT ;
    USE SIGNAL ;
    PORT
      LAYER M4 ;
        RECT  0 29.376 0.084 29.4 ;
    END
  END a[39]
  PIN a[3]
    DIRECTION INPUT ;
    USE SIGNAL ;
    PORT
      LAYER M4 ;
        RECT  0 42.624 0.084 42.648 ;
    END
  END a[3]
  PIN a[40]
    DIRECTION INPUT ;
    USE SIGNAL ;
    PORT
      LAYER M4 ;
        RECT  0 29.52 0.084 29.544 ;
    END
  END a[40]
  PIN a[41]
    DIRECTION INPUT ;
    USE SIGNAL ;
    PORT
      LAYER M4 ;
        RECT  0 29.664 0.084 29.688 ;
    END
  END a[41]
  PIN a[42]
    DIRECTION INPUT ;
    USE SIGNAL ;
    PORT
      LAYER M4 ;
        RECT  0 29.808 0.084 29.832 ;
    END
  END a[42]
  PIN a[43]
    DIRECTION INPUT ;
    USE SIGNAL ;
    PORT
      LAYER M4 ;
        RECT  0 29.952 0.084 29.976 ;
    END
  END a[43]
  PIN a[44]
    DIRECTION INPUT ;
    USE SIGNAL ;
    PORT
      LAYER M4 ;
        RECT  0 30.096 0.084 30.12 ;
    END
  END a[44]
  PIN a[45]
    DIRECTION INPUT ;
    USE SIGNAL ;
    PORT
      LAYER M4 ;
        RECT  0 30.24 0.084 30.264 ;
    END
  END a[45]
  PIN a[46]
    DIRECTION INPUT ;
    USE SIGNAL ;
    PORT
      LAYER M4 ;
        RECT  0 30.384 0.084 30.408 ;
    END
  END a[46]
  PIN a[47]
    DIRECTION INPUT ;
    USE SIGNAL ;
    PORT
      LAYER M4 ;
        RECT  0 30.528 0.084 30.552 ;
    END
  END a[47]
  PIN a[48]
    DIRECTION INPUT ;
    USE SIGNAL ;
    PORT
      LAYER M4 ;
        RECT  0 30.672 0.084 30.696 ;
    END
  END a[48]
  PIN a[49]
    DIRECTION INPUT ;
    USE SIGNAL ;
    PORT
      LAYER M4 ;
        RECT  0 30.816 0.084 30.84 ;
    END
  END a[49]
  PIN a[4]
    DIRECTION INPUT ;
    USE SIGNAL ;
    PORT
      LAYER M4 ;
        RECT  0 42.768 0.084 42.792 ;
    END
  END a[4]
  PIN a[50]
    DIRECTION INPUT ;
    USE SIGNAL ;
    PORT
      LAYER M4 ;
        RECT  0 30.96 0.084 30.984 ;
    END
  END a[50]
  PIN a[51]
    DIRECTION INPUT ;
    USE SIGNAL ;
    PORT
      LAYER M4 ;
        RECT  0 31.104 0.084 31.128 ;
    END
  END a[51]
  PIN a[52]
    DIRECTION INPUT ;
    USE SIGNAL ;
    PORT
      LAYER M4 ;
        RECT  0 31.248 0.084 31.272 ;
    END
  END a[52]
  PIN a[53]
    DIRECTION INPUT ;
    USE SIGNAL ;
    PORT
      LAYER M4 ;
        RECT  0 31.392 0.084 31.416 ;
    END
  END a[53]
  PIN a[54]
    DIRECTION INPUT ;
    USE SIGNAL ;
    PORT
      LAYER M4 ;
        RECT  0 31.536 0.084 31.56 ;
    END
  END a[54]
  PIN a[55]
    DIRECTION INPUT ;
    USE SIGNAL ;
    PORT
      LAYER M4 ;
        RECT  0 31.68 0.084 31.704 ;
    END
  END a[55]
  PIN a[56]
    DIRECTION INPUT ;
    USE SIGNAL ;
    PORT
      LAYER M4 ;
        RECT  0 31.824 0.084 31.848 ;
    END
  END a[56]
  PIN a[57]
    DIRECTION INPUT ;
    USE SIGNAL ;
    PORT
      LAYER M4 ;
        RECT  0 31.968 0.084 31.992 ;
    END
  END a[57]
  PIN a[58]
    DIRECTION INPUT ;
    USE SIGNAL ;
    PORT
      LAYER M4 ;
        RECT  0 32.112 0.084 32.136 ;
    END
  END a[58]
  PIN a[59]
    DIRECTION INPUT ;
    USE SIGNAL ;
    PORT
      LAYER M4 ;
        RECT  0 32.256 0.084 32.28 ;
    END
  END a[59]
  PIN a[5]
    DIRECTION INPUT ;
    USE SIGNAL ;
    PORT
      LAYER M4 ;
        RECT  0 42.912 0.084 42.936 ;
    END
  END a[5]
  PIN a[60]
    DIRECTION INPUT ;
    USE SIGNAL ;
    PORT
      LAYER M4 ;
        RECT  0 32.4 0.084 32.424 ;
    END
  END a[60]
  PIN a[61]
    DIRECTION INPUT ;
    USE SIGNAL ;
    PORT
      LAYER M4 ;
        RECT  0 32.544 0.084 32.568 ;
    END
  END a[61]
  PIN a[62]
    DIRECTION INPUT ;
    USE SIGNAL ;
    PORT
      LAYER M4 ;
        RECT  0 32.688 0.084 32.712 ;
    END
  END a[62]
  PIN a[63]
    DIRECTION INPUT ;
    USE SIGNAL ;
    PORT
      LAYER M4 ;
        RECT  0 32.832 0.084 32.856 ;
    END
  END a[63]
  PIN a[64]
    DIRECTION INPUT ;
    USE SIGNAL ;
    PORT
      LAYER M4 ;
        RECT  0 23.76 0.084 23.784 ;
    END
  END a[64]
  PIN a[65]
    DIRECTION INPUT ;
    USE SIGNAL ;
    PORT
      LAYER M4 ;
        RECT  0 23.904 0.084 23.928 ;
    END
  END a[65]
  PIN a[66]
    DIRECTION INPUT ;
    USE SIGNAL ;
    PORT
      LAYER M4 ;
        RECT  0 24.048 0.084 24.072 ;
    END
  END a[66]
  PIN a[67]
    DIRECTION INPUT ;
    USE SIGNAL ;
    PORT
      LAYER M4 ;
        RECT  0 24.192 0.084 24.216 ;
    END
  END a[67]
  PIN a[68]
    DIRECTION INPUT ;
    USE SIGNAL ;
    PORT
      LAYER M4 ;
        RECT  0 24.336 0.084 24.36 ;
    END
  END a[68]
  PIN a[69]
    DIRECTION INPUT ;
    USE SIGNAL ;
    PORT
      LAYER M4 ;
        RECT  0 24.48 0.084 24.504 ;
    END
  END a[69]
  PIN a[6]
    DIRECTION INPUT ;
    USE SIGNAL ;
    PORT
      LAYER M4 ;
        RECT  0 43.056 0.084 43.08 ;
    END
  END a[6]
  PIN a[70]
    DIRECTION INPUT ;
    USE SIGNAL ;
    PORT
      LAYER M4 ;
        RECT  0 24.624 0.084 24.648 ;
    END
  END a[70]
  PIN a[71]
    DIRECTION INPUT ;
    USE SIGNAL ;
    PORT
      LAYER M4 ;
        RECT  0 24.768 0.084 24.792 ;
    END
  END a[71]
  PIN a[72]
    DIRECTION INPUT ;
    USE SIGNAL ;
    PORT
      LAYER M4 ;
        RECT  0 24.912 0.084 24.936 ;
    END
  END a[72]
  PIN a[73]
    DIRECTION INPUT ;
    USE SIGNAL ;
    PORT
      LAYER M4 ;
        RECT  0 25.056 0.084 25.08 ;
    END
  END a[73]
  PIN a[74]
    DIRECTION INPUT ;
    USE SIGNAL ;
    PORT
      LAYER M4 ;
        RECT  0 25.2 0.084 25.224 ;
    END
  END a[74]
  PIN a[75]
    DIRECTION INPUT ;
    USE SIGNAL ;
    PORT
      LAYER M4 ;
        RECT  0 25.344 0.084 25.368 ;
    END
  END a[75]
  PIN a[76]
    DIRECTION INPUT ;
    USE SIGNAL ;
    PORT
      LAYER M4 ;
        RECT  0 25.488 0.084 25.512 ;
    END
  END a[76]
  PIN a[77]
    DIRECTION INPUT ;
    USE SIGNAL ;
    PORT
      LAYER M4 ;
        RECT  0 25.632 0.084 25.656 ;
    END
  END a[77]
  PIN a[78]
    DIRECTION INPUT ;
    USE SIGNAL ;
    PORT
      LAYER M4 ;
        RECT  0 25.776 0.084 25.8 ;
    END
  END a[78]
  PIN a[79]
    DIRECTION INPUT ;
    USE SIGNAL ;
    PORT
      LAYER M4 ;
        RECT  0 25.92 0.084 25.944 ;
    END
  END a[79]
  PIN a[7]
    DIRECTION INPUT ;
    USE SIGNAL ;
    PORT
      LAYER M4 ;
        RECT  0 43.2 0.084 43.224 ;
    END
  END a[7]
  PIN a[80]
    DIRECTION INPUT ;
    USE SIGNAL ;
    PORT
      LAYER M4 ;
        RECT  0 26.064 0.084 26.088 ;
    END
  END a[80]
  PIN a[81]
    DIRECTION INPUT ;
    USE SIGNAL ;
    PORT
      LAYER M4 ;
        RECT  0 26.208 0.084 26.232 ;
    END
  END a[81]
  PIN a[82]
    DIRECTION INPUT ;
    USE SIGNAL ;
    PORT
      LAYER M4 ;
        RECT  0 26.352 0.084 26.376 ;
    END
  END a[82]
  PIN a[83]
    DIRECTION INPUT ;
    USE SIGNAL ;
    PORT
      LAYER M4 ;
        RECT  0 26.496 0.084 26.52 ;
    END
  END a[83]
  PIN a[84]
    DIRECTION INPUT ;
    USE SIGNAL ;
    PORT
      LAYER M4 ;
        RECT  0 26.64 0.084 26.664 ;
    END
  END a[84]
  PIN a[85]
    DIRECTION INPUT ;
    USE SIGNAL ;
    PORT
      LAYER M4 ;
        RECT  0 26.784 0.084 26.808 ;
    END
  END a[85]
  PIN a[86]
    DIRECTION INPUT ;
    USE SIGNAL ;
    PORT
      LAYER M4 ;
        RECT  0 26.928 0.084 26.952 ;
    END
  END a[86]
  PIN a[87]
    DIRECTION INPUT ;
    USE SIGNAL ;
    PORT
      LAYER M4 ;
        RECT  0 27.072 0.084 27.096 ;
    END
  END a[87]
  PIN a[88]
    DIRECTION INPUT ;
    USE SIGNAL ;
    PORT
      LAYER M4 ;
        RECT  0 27.216 0.084 27.24 ;
    END
  END a[88]
  PIN a[89]
    DIRECTION INPUT ;
    USE SIGNAL ;
    PORT
      LAYER M4 ;
        RECT  0 27.36 0.084 27.384 ;
    END
  END a[89]
  PIN a[8]
    DIRECTION INPUT ;
    USE SIGNAL ;
    PORT
      LAYER M4 ;
        RECT  0 43.344 0.084 43.368 ;
    END
  END a[8]
  PIN a[90]
    DIRECTION INPUT ;
    USE SIGNAL ;
    PORT
      LAYER M4 ;
        RECT  0 27.504 0.084 27.528 ;
    END
  END a[90]
  PIN a[91]
    DIRECTION INPUT ;
    USE SIGNAL ;
    PORT
      LAYER M4 ;
        RECT  0 27.648 0.084 27.672 ;
    END
  END a[91]
  PIN a[92]
    DIRECTION INPUT ;
    USE SIGNAL ;
    PORT
      LAYER M4 ;
        RECT  0 27.792 0.084 27.816 ;
    END
  END a[92]
  PIN a[93]
    DIRECTION INPUT ;
    USE SIGNAL ;
    PORT
      LAYER M4 ;
        RECT  0 27.936 0.084 27.96 ;
    END
  END a[93]
  PIN a[94]
    DIRECTION INPUT ;
    USE SIGNAL ;
    PORT
      LAYER M4 ;
        RECT  0 28.08 0.084 28.104 ;
    END
  END a[94]
  PIN a[95]
    DIRECTION INPUT ;
    USE SIGNAL ;
    PORT
      LAYER M4 ;
        RECT  0 28.224 0.084 28.248 ;
    END
  END a[95]
  PIN a[96]
    DIRECTION INPUT ;
    USE SIGNAL ;
    PORT
      LAYER M4 ;
        RECT  0 37.584 0.084 37.608 ;
    END
  END a[96]
  PIN a[97]
    DIRECTION INPUT ;
    USE SIGNAL ;
    PORT
      LAYER M4 ;
        RECT  0 37.728 0.084 37.752 ;
    END
  END a[97]
  PIN a[98]
    DIRECTION INPUT ;
    USE SIGNAL ;
    PORT
      LAYER M4 ;
        RECT  0 37.872 0.084 37.896 ;
    END
  END a[98]
  PIN a[99]
    DIRECTION INPUT ;
    USE SIGNAL ;
    PORT
      LAYER M4 ;
        RECT  0 38.016 0.084 38.04 ;
    END
  END a[99]
  PIN a[9]
    DIRECTION INPUT ;
    USE SIGNAL ;
    PORT
      LAYER M4 ;
        RECT  0 43.488 0.084 43.512 ;
    END
  END a[9]
  PIN b[0]
    DIRECTION OUTPUT ;
    USE SIGNAL ;
    PORT
      LAYER M4 ;
        RECT  21.516 0.72 21.6 0.744 ;
    END
  END b[0]
  PIN b[100]
    DIRECTION OUTPUT ;
    USE SIGNAL ;
    PORT
      LAYER M4 ;
        RECT  21.516 10.512 21.6 10.536 ;
    END
  END b[100]
  PIN b[101]
    DIRECTION OUTPUT ;
    USE SIGNAL ;
    PORT
      LAYER M4 ;
        RECT  21.516 10.656 21.6 10.68 ;
    END
  END b[101]
  PIN b[102]
    DIRECTION OUTPUT ;
    USE SIGNAL ;
    PORT
      LAYER M4 ;
        RECT  21.516 10.8 21.6 10.824 ;
    END
  END b[102]
  PIN b[103]
    DIRECTION OUTPUT ;
    USE SIGNAL ;
    PORT
      LAYER M4 ;
        RECT  21.516 10.944 21.6 10.968 ;
    END
  END b[103]
  PIN b[104]
    DIRECTION OUTPUT ;
    USE SIGNAL ;
    PORT
      LAYER M4 ;
        RECT  21.516 11.088 21.6 11.112 ;
    END
  END b[104]
  PIN b[105]
    DIRECTION OUTPUT ;
    USE SIGNAL ;
    PORT
      LAYER M4 ;
        RECT  21.516 11.232 21.6 11.256 ;
    END
  END b[105]
  PIN b[106]
    DIRECTION OUTPUT ;
    USE SIGNAL ;
    PORT
      LAYER M4 ;
        RECT  21.516 11.376 21.6 11.4 ;
    END
  END b[106]
  PIN b[107]
    DIRECTION OUTPUT ;
    USE SIGNAL ;
    PORT
      LAYER M4 ;
        RECT  21.516 11.52 21.6 11.544 ;
    END
  END b[107]
  PIN b[108]
    DIRECTION OUTPUT ;
    USE SIGNAL ;
    PORT
      LAYER M4 ;
        RECT  21.516 11.664 21.6 11.688 ;
    END
  END b[108]
  PIN b[109]
    DIRECTION OUTPUT ;
    USE SIGNAL ;
    PORT
      LAYER M4 ;
        RECT  21.516 11.808 21.6 11.832 ;
    END
  END b[109]
  PIN b[10]
    DIRECTION OUTPUT ;
    USE SIGNAL ;
    PORT
      LAYER M4 ;
        RECT  21.516 2.16 21.6 2.184 ;
    END
  END b[10]
  PIN b[110]
    DIRECTION OUTPUT ;
    USE SIGNAL ;
    PORT
      LAYER M4 ;
        RECT  21.516 11.952 21.6 11.976 ;
    END
  END b[110]
  PIN b[111]
    DIRECTION OUTPUT ;
    USE SIGNAL ;
    PORT
      LAYER M4 ;
        RECT  21.516 12.096 21.6 12.12 ;
    END
  END b[111]
  PIN b[112]
    DIRECTION OUTPUT ;
    USE SIGNAL ;
    PORT
      LAYER M4 ;
        RECT  21.516 12.24 21.6 12.264 ;
    END
  END b[112]
  PIN b[113]
    DIRECTION OUTPUT ;
    USE SIGNAL ;
    PORT
      LAYER M4 ;
        RECT  21.516 12.384 21.6 12.408 ;
    END
  END b[113]
  PIN b[114]
    DIRECTION OUTPUT ;
    USE SIGNAL ;
    PORT
      LAYER M4 ;
        RECT  21.516 12.528 21.6 12.552 ;
    END
  END b[114]
  PIN b[115]
    DIRECTION OUTPUT ;
    USE SIGNAL ;
    PORT
      LAYER M4 ;
        RECT  21.516 12.672 21.6 12.696 ;
    END
  END b[115]
  PIN b[116]
    DIRECTION OUTPUT ;
    USE SIGNAL ;
    PORT
      LAYER M4 ;
        RECT  21.516 12.816 21.6 12.84 ;
    END
  END b[116]
  PIN b[117]
    DIRECTION OUTPUT ;
    USE SIGNAL ;
    PORT
      LAYER M4 ;
        RECT  21.516 12.96 21.6 12.984 ;
    END
  END b[117]
  PIN b[118]
    DIRECTION OUTPUT ;
    USE SIGNAL ;
    PORT
      LAYER M4 ;
        RECT  21.516 13.104 21.6 13.128 ;
    END
  END b[118]
  PIN b[119]
    DIRECTION OUTPUT ;
    USE SIGNAL ;
    PORT
      LAYER M4 ;
        RECT  21.516 13.248 21.6 13.272 ;
    END
  END b[119]
  PIN b[11]
    DIRECTION OUTPUT ;
    USE SIGNAL ;
    PORT
      LAYER M4 ;
        RECT  21.516 2.304 21.6 2.328 ;
    END
  END b[11]
  PIN b[120]
    DIRECTION OUTPUT ;
    USE SIGNAL ;
    PORT
      LAYER M4 ;
        RECT  21.516 13.392 21.6 13.416 ;
    END
  END b[120]
  PIN b[121]
    DIRECTION OUTPUT ;
    USE SIGNAL ;
    PORT
      LAYER M4 ;
        RECT  21.516 13.536 21.6 13.56 ;
    END
  END b[121]
  PIN b[122]
    DIRECTION OUTPUT ;
    USE SIGNAL ;
    PORT
      LAYER M4 ;
        RECT  21.516 13.68 21.6 13.704 ;
    END
  END b[122]
  PIN b[123]
    DIRECTION OUTPUT ;
    USE SIGNAL ;
    PORT
      LAYER M4 ;
        RECT  21.516 13.824 21.6 13.848 ;
    END
  END b[123]
  PIN b[124]
    DIRECTION OUTPUT ;
    USE SIGNAL ;
    PORT
      LAYER M4 ;
        RECT  21.516 13.968 21.6 13.992 ;
    END
  END b[124]
  PIN b[125]
    DIRECTION OUTPUT ;
    USE SIGNAL ;
    PORT
      LAYER M4 ;
        RECT  21.516 14.112 21.6 14.136 ;
    END
  END b[125]
  PIN b[126]
    DIRECTION OUTPUT ;
    USE SIGNAL ;
    PORT
      LAYER M4 ;
        RECT  21.516 14.256 21.6 14.28 ;
    END
  END b[126]
  PIN b[127]
    DIRECTION OUTPUT ;
    USE SIGNAL ;
    PORT
      LAYER M4 ;
        RECT  21.516 14.4 21.6 14.424 ;
    END
  END b[127]
  PIN b[128]
    DIRECTION OUTPUT ;
    USE SIGNAL ;
    PORT
      LAYER M4 ;
        RECT  21.516 23.76 21.6 23.784 ;
    END
  END b[128]
  PIN b[129]
    DIRECTION OUTPUT ;
    USE SIGNAL ;
    PORT
      LAYER M4 ;
        RECT  21.516 23.904 21.6 23.928 ;
    END
  END b[129]
  PIN b[12]
    DIRECTION OUTPUT ;
    USE SIGNAL ;
    PORT
      LAYER M4 ;
        RECT  21.516 2.448 21.6 2.472 ;
    END
  END b[12]
  PIN b[130]
    DIRECTION OUTPUT ;
    USE SIGNAL ;
    PORT
      LAYER M4 ;
        RECT  21.516 24.048 21.6 24.072 ;
    END
  END b[130]
  PIN b[131]
    DIRECTION OUTPUT ;
    USE SIGNAL ;
    PORT
      LAYER M4 ;
        RECT  21.516 24.192 21.6 24.216 ;
    END
  END b[131]
  PIN b[132]
    DIRECTION OUTPUT ;
    USE SIGNAL ;
    PORT
      LAYER M4 ;
        RECT  21.516 24.336 21.6 24.36 ;
    END
  END b[132]
  PIN b[133]
    DIRECTION OUTPUT ;
    USE SIGNAL ;
    PORT
      LAYER M4 ;
        RECT  21.516 24.48 21.6 24.504 ;
    END
  END b[133]
  PIN b[134]
    DIRECTION OUTPUT ;
    USE SIGNAL ;
    PORT
      LAYER M4 ;
        RECT  21.516 24.624 21.6 24.648 ;
    END
  END b[134]
  PIN b[135]
    DIRECTION OUTPUT ;
    USE SIGNAL ;
    PORT
      LAYER M4 ;
        RECT  21.516 24.768 21.6 24.792 ;
    END
  END b[135]
  PIN b[136]
    DIRECTION OUTPUT ;
    USE SIGNAL ;
    PORT
      LAYER M4 ;
        RECT  21.516 24.912 21.6 24.936 ;
    END
  END b[136]
  PIN b[137]
    DIRECTION OUTPUT ;
    USE SIGNAL ;
    PORT
      LAYER M4 ;
        RECT  21.516 25.056 21.6 25.08 ;
    END
  END b[137]
  PIN b[138]
    DIRECTION OUTPUT ;
    USE SIGNAL ;
    PORT
      LAYER M4 ;
        RECT  21.516 25.2 21.6 25.224 ;
    END
  END b[138]
  PIN b[139]
    DIRECTION OUTPUT ;
    USE SIGNAL ;
    PORT
      LAYER M4 ;
        RECT  21.516 25.344 21.6 25.368 ;
    END
  END b[139]
  PIN b[13]
    DIRECTION OUTPUT ;
    USE SIGNAL ;
    PORT
      LAYER M4 ;
        RECT  21.516 2.592 21.6 2.616 ;
    END
  END b[13]
  PIN b[140]
    DIRECTION OUTPUT ;
    USE SIGNAL ;
    PORT
      LAYER M4 ;
        RECT  21.516 25.488 21.6 25.512 ;
    END
  END b[140]
  PIN b[141]
    DIRECTION OUTPUT ;
    USE SIGNAL ;
    PORT
      LAYER M4 ;
        RECT  21.516 25.632 21.6 25.656 ;
    END
  END b[141]
  PIN b[142]
    DIRECTION OUTPUT ;
    USE SIGNAL ;
    PORT
      LAYER M4 ;
        RECT  21.516 25.776 21.6 25.8 ;
    END
  END b[142]
  PIN b[143]
    DIRECTION OUTPUT ;
    USE SIGNAL ;
    PORT
      LAYER M4 ;
        RECT  21.516 25.92 21.6 25.944 ;
    END
  END b[143]
  PIN b[144]
    DIRECTION OUTPUT ;
    USE SIGNAL ;
    PORT
      LAYER M4 ;
        RECT  21.516 26.064 21.6 26.088 ;
    END
  END b[144]
  PIN b[145]
    DIRECTION OUTPUT ;
    USE SIGNAL ;
    PORT
      LAYER M4 ;
        RECT  21.516 26.208 21.6 26.232 ;
    END
  END b[145]
  PIN b[146]
    DIRECTION OUTPUT ;
    USE SIGNAL ;
    PORT
      LAYER M4 ;
        RECT  21.516 26.352 21.6 26.376 ;
    END
  END b[146]
  PIN b[147]
    DIRECTION OUTPUT ;
    USE SIGNAL ;
    PORT
      LAYER M4 ;
        RECT  21.516 26.496 21.6 26.52 ;
    END
  END b[147]
  PIN b[148]
    DIRECTION OUTPUT ;
    USE SIGNAL ;
    PORT
      LAYER M4 ;
        RECT  21.516 26.64 21.6 26.664 ;
    END
  END b[148]
  PIN b[149]
    DIRECTION OUTPUT ;
    USE SIGNAL ;
    PORT
      LAYER M4 ;
        RECT  21.516 26.784 21.6 26.808 ;
    END
  END b[149]
  PIN b[14]
    DIRECTION OUTPUT ;
    USE SIGNAL ;
    PORT
      LAYER M4 ;
        RECT  21.516 2.736 21.6 2.76 ;
    END
  END b[14]
  PIN b[150]
    DIRECTION OUTPUT ;
    USE SIGNAL ;
    PORT
      LAYER M4 ;
        RECT  21.516 26.928 21.6 26.952 ;
    END
  END b[150]
  PIN b[151]
    DIRECTION OUTPUT ;
    USE SIGNAL ;
    PORT
      LAYER M4 ;
        RECT  21.516 27.072 21.6 27.096 ;
    END
  END b[151]
  PIN b[152]
    DIRECTION OUTPUT ;
    USE SIGNAL ;
    PORT
      LAYER M4 ;
        RECT  21.516 27.216 21.6 27.24 ;
    END
  END b[152]
  PIN b[153]
    DIRECTION OUTPUT ;
    USE SIGNAL ;
    PORT
      LAYER M4 ;
        RECT  21.516 27.36 21.6 27.384 ;
    END
  END b[153]
  PIN b[154]
    DIRECTION OUTPUT ;
    USE SIGNAL ;
    PORT
      LAYER M4 ;
        RECT  21.516 27.504 21.6 27.528 ;
    END
  END b[154]
  PIN b[155]
    DIRECTION OUTPUT ;
    USE SIGNAL ;
    PORT
      LAYER M4 ;
        RECT  21.516 27.648 21.6 27.672 ;
    END
  END b[155]
  PIN b[156]
    DIRECTION OUTPUT ;
    USE SIGNAL ;
    PORT
      LAYER M4 ;
        RECT  21.516 27.792 21.6 27.816 ;
    END
  END b[156]
  PIN b[157]
    DIRECTION OUTPUT ;
    USE SIGNAL ;
    PORT
      LAYER M4 ;
        RECT  21.516 27.936 21.6 27.96 ;
    END
  END b[157]
  PIN b[158]
    DIRECTION OUTPUT ;
    USE SIGNAL ;
    PORT
      LAYER M4 ;
        RECT  21.516 28.08 21.6 28.104 ;
    END
  END b[158]
  PIN b[159]
    DIRECTION OUTPUT ;
    USE SIGNAL ;
    PORT
      LAYER M4 ;
        RECT  21.516 28.224 21.6 28.248 ;
    END
  END b[159]
  PIN b[15]
    DIRECTION OUTPUT ;
    USE SIGNAL ;
    PORT
      LAYER M4 ;
        RECT  21.516 2.88 21.6 2.904 ;
    END
  END b[15]
  PIN b[160]
    DIRECTION OUTPUT ;
    USE SIGNAL ;
    PORT
      LAYER M4 ;
        RECT  21.516 14.544 21.6 14.568 ;
    END
  END b[160]
  PIN b[161]
    DIRECTION OUTPUT ;
    USE SIGNAL ;
    PORT
      LAYER M4 ;
        RECT  21.516 14.688 21.6 14.712 ;
    END
  END b[161]
  PIN b[162]
    DIRECTION OUTPUT ;
    USE SIGNAL ;
    PORT
      LAYER M4 ;
        RECT  21.516 14.832 21.6 14.856 ;
    END
  END b[162]
  PIN b[163]
    DIRECTION OUTPUT ;
    USE SIGNAL ;
    PORT
      LAYER M4 ;
        RECT  21.516 14.976 21.6 15 ;
    END
  END b[163]
  PIN b[164]
    DIRECTION OUTPUT ;
    USE SIGNAL ;
    PORT
      LAYER M4 ;
        RECT  21.516 15.12 21.6 15.144 ;
    END
  END b[164]
  PIN b[165]
    DIRECTION OUTPUT ;
    USE SIGNAL ;
    PORT
      LAYER M4 ;
        RECT  21.516 15.264 21.6 15.288 ;
    END
  END b[165]
  PIN b[166]
    DIRECTION OUTPUT ;
    USE SIGNAL ;
    PORT
      LAYER M4 ;
        RECT  21.516 15.408 21.6 15.432 ;
    END
  END b[166]
  PIN b[167]
    DIRECTION OUTPUT ;
    USE SIGNAL ;
    PORT
      LAYER M4 ;
        RECT  21.516 15.552 21.6 15.576 ;
    END
  END b[167]
  PIN b[168]
    DIRECTION OUTPUT ;
    USE SIGNAL ;
    PORT
      LAYER M4 ;
        RECT  21.516 15.696 21.6 15.72 ;
    END
  END b[168]
  PIN b[169]
    DIRECTION OUTPUT ;
    USE SIGNAL ;
    PORT
      LAYER M4 ;
        RECT  21.516 15.84 21.6 15.864 ;
    END
  END b[169]
  PIN b[16]
    DIRECTION OUTPUT ;
    USE SIGNAL ;
    PORT
      LAYER M4 ;
        RECT  21.516 3.024 21.6 3.048 ;
    END
  END b[16]
  PIN b[170]
    DIRECTION OUTPUT ;
    USE SIGNAL ;
    PORT
      LAYER M4 ;
        RECT  21.516 15.984 21.6 16.008 ;
    END
  END b[170]
  PIN b[171]
    DIRECTION OUTPUT ;
    USE SIGNAL ;
    PORT
      LAYER M4 ;
        RECT  21.516 16.128 21.6 16.152 ;
    END
  END b[171]
  PIN b[172]
    DIRECTION OUTPUT ;
    USE SIGNAL ;
    PORT
      LAYER M4 ;
        RECT  21.516 16.272 21.6 16.296 ;
    END
  END b[172]
  PIN b[173]
    DIRECTION OUTPUT ;
    USE SIGNAL ;
    PORT
      LAYER M4 ;
        RECT  21.516 16.416 21.6 16.44 ;
    END
  END b[173]
  PIN b[174]
    DIRECTION OUTPUT ;
    USE SIGNAL ;
    PORT
      LAYER M4 ;
        RECT  21.516 16.56 21.6 16.584 ;
    END
  END b[174]
  PIN b[175]
    DIRECTION OUTPUT ;
    USE SIGNAL ;
    PORT
      LAYER M4 ;
        RECT  21.516 16.704 21.6 16.728 ;
    END
  END b[175]
  PIN b[176]
    DIRECTION OUTPUT ;
    USE SIGNAL ;
    PORT
      LAYER M4 ;
        RECT  21.516 16.848 21.6 16.872 ;
    END
  END b[176]
  PIN b[177]
    DIRECTION OUTPUT ;
    USE SIGNAL ;
    PORT
      LAYER M4 ;
        RECT  21.516 16.992 21.6 17.016 ;
    END
  END b[177]
  PIN b[178]
    DIRECTION OUTPUT ;
    USE SIGNAL ;
    PORT
      LAYER M4 ;
        RECT  21.516 17.136 21.6 17.16 ;
    END
  END b[178]
  PIN b[179]
    DIRECTION OUTPUT ;
    USE SIGNAL ;
    PORT
      LAYER M4 ;
        RECT  21.516 17.28 21.6 17.304 ;
    END
  END b[179]
  PIN b[17]
    DIRECTION OUTPUT ;
    USE SIGNAL ;
    PORT
      LAYER M4 ;
        RECT  21.516 3.168 21.6 3.192 ;
    END
  END b[17]
  PIN b[180]
    DIRECTION OUTPUT ;
    USE SIGNAL ;
    PORT
      LAYER M4 ;
        RECT  21.516 17.424 21.6 17.448 ;
    END
  END b[180]
  PIN b[181]
    DIRECTION OUTPUT ;
    USE SIGNAL ;
    PORT
      LAYER M4 ;
        RECT  21.516 17.568 21.6 17.592 ;
    END
  END b[181]
  PIN b[182]
    DIRECTION OUTPUT ;
    USE SIGNAL ;
    PORT
      LAYER M4 ;
        RECT  21.516 17.712 21.6 17.736 ;
    END
  END b[182]
  PIN b[183]
    DIRECTION OUTPUT ;
    USE SIGNAL ;
    PORT
      LAYER M4 ;
        RECT  21.516 17.856 21.6 17.88 ;
    END
  END b[183]
  PIN b[184]
    DIRECTION OUTPUT ;
    USE SIGNAL ;
    PORT
      LAYER M4 ;
        RECT  21.516 18 21.6 18.024 ;
    END
  END b[184]
  PIN b[185]
    DIRECTION OUTPUT ;
    USE SIGNAL ;
    PORT
      LAYER M4 ;
        RECT  21.516 18.144 21.6 18.168 ;
    END
  END b[185]
  PIN b[186]
    DIRECTION OUTPUT ;
    USE SIGNAL ;
    PORT
      LAYER M4 ;
        RECT  21.516 18.288 21.6 18.312 ;
    END
  END b[186]
  PIN b[187]
    DIRECTION OUTPUT ;
    USE SIGNAL ;
    PORT
      LAYER M4 ;
        RECT  21.516 18.432 21.6 18.456 ;
    END
  END b[187]
  PIN b[188]
    DIRECTION OUTPUT ;
    USE SIGNAL ;
    PORT
      LAYER M4 ;
        RECT  21.516 18.576 21.6 18.6 ;
    END
  END b[188]
  PIN b[189]
    DIRECTION OUTPUT ;
    USE SIGNAL ;
    PORT
      LAYER M4 ;
        RECT  21.516 18.72 21.6 18.744 ;
    END
  END b[189]
  PIN b[18]
    DIRECTION OUTPUT ;
    USE SIGNAL ;
    PORT
      LAYER M4 ;
        RECT  21.516 3.312 21.6 3.336 ;
    END
  END b[18]
  PIN b[190]
    DIRECTION OUTPUT ;
    USE SIGNAL ;
    PORT
      LAYER M4 ;
        RECT  21.516 18.864 21.6 18.888 ;
    END
  END b[190]
  PIN b[191]
    DIRECTION OUTPUT ;
    USE SIGNAL ;
    PORT
      LAYER M4 ;
        RECT  21.516 19.008 21.6 19.032 ;
    END
  END b[191]
  PIN b[192]
    DIRECTION OUTPUT ;
    USE SIGNAL ;
    PORT
      LAYER M4 ;
        RECT  21.516 29.52 21.6 29.544 ;
    END
  END b[192]
  PIN b[193]
    DIRECTION OUTPUT ;
    USE SIGNAL ;
    PORT
      LAYER M4 ;
        RECT  21.516 29.664 21.6 29.688 ;
    END
  END b[193]
  PIN b[194]
    DIRECTION OUTPUT ;
    USE SIGNAL ;
    PORT
      LAYER M4 ;
        RECT  21.516 29.808 21.6 29.832 ;
    END
  END b[194]
  PIN b[195]
    DIRECTION OUTPUT ;
    USE SIGNAL ;
    PORT
      LAYER M4 ;
        RECT  21.516 29.952 21.6 29.976 ;
    END
  END b[195]
  PIN b[196]
    DIRECTION OUTPUT ;
    USE SIGNAL ;
    PORT
      LAYER M4 ;
        RECT  21.516 30.096 21.6 30.12 ;
    END
  END b[196]
  PIN b[197]
    DIRECTION OUTPUT ;
    USE SIGNAL ;
    PORT
      LAYER M4 ;
        RECT  21.516 30.24 21.6 30.264 ;
    END
  END b[197]
  PIN b[198]
    DIRECTION OUTPUT ;
    USE SIGNAL ;
    PORT
      LAYER M4 ;
        RECT  21.516 30.384 21.6 30.408 ;
    END
  END b[198]
  PIN b[199]
    DIRECTION OUTPUT ;
    USE SIGNAL ;
    PORT
      LAYER M4 ;
        RECT  21.516 30.528 21.6 30.552 ;
    END
  END b[199]
  PIN b[19]
    DIRECTION OUTPUT ;
    USE SIGNAL ;
    PORT
      LAYER M4 ;
        RECT  21.516 3.456 21.6 3.48 ;
    END
  END b[19]
  PIN b[1]
    DIRECTION OUTPUT ;
    USE SIGNAL ;
    PORT
      LAYER M4 ;
        RECT  21.516 0.864 21.6 0.888 ;
    END
  END b[1]
  PIN b[200]
    DIRECTION OUTPUT ;
    USE SIGNAL ;
    PORT
      LAYER M4 ;
        RECT  21.516 30.672 21.6 30.696 ;
    END
  END b[200]
  PIN b[201]
    DIRECTION OUTPUT ;
    USE SIGNAL ;
    PORT
      LAYER M4 ;
        RECT  21.516 30.816 21.6 30.84 ;
    END
  END b[201]
  PIN b[202]
    DIRECTION OUTPUT ;
    USE SIGNAL ;
    PORT
      LAYER M4 ;
        RECT  21.516 30.96 21.6 30.984 ;
    END
  END b[202]
  PIN b[203]
    DIRECTION OUTPUT ;
    USE SIGNAL ;
    PORT
      LAYER M4 ;
        RECT  21.516 31.104 21.6 31.128 ;
    END
  END b[203]
  PIN b[204]
    DIRECTION OUTPUT ;
    USE SIGNAL ;
    PORT
      LAYER M4 ;
        RECT  21.516 31.248 21.6 31.272 ;
    END
  END b[204]
  PIN b[205]
    DIRECTION OUTPUT ;
    USE SIGNAL ;
    PORT
      LAYER M4 ;
        RECT  21.516 31.392 21.6 31.416 ;
    END
  END b[205]
  PIN b[206]
    DIRECTION OUTPUT ;
    USE SIGNAL ;
    PORT
      LAYER M4 ;
        RECT  21.516 31.536 21.6 31.56 ;
    END
  END b[206]
  PIN b[207]
    DIRECTION OUTPUT ;
    USE SIGNAL ;
    PORT
      LAYER M4 ;
        RECT  21.516 31.68 21.6 31.704 ;
    END
  END b[207]
  PIN b[208]
    DIRECTION OUTPUT ;
    USE SIGNAL ;
    PORT
      LAYER M4 ;
        RECT  21.516 31.824 21.6 31.848 ;
    END
  END b[208]
  PIN b[209]
    DIRECTION OUTPUT ;
    USE SIGNAL ;
    PORT
      LAYER M4 ;
        RECT  21.516 31.968 21.6 31.992 ;
    END
  END b[209]
  PIN b[20]
    DIRECTION OUTPUT ;
    USE SIGNAL ;
    PORT
      LAYER M4 ;
        RECT  21.516 3.6 21.6 3.624 ;
    END
  END b[20]
  PIN b[210]
    DIRECTION OUTPUT ;
    USE SIGNAL ;
    PORT
      LAYER M4 ;
        RECT  21.516 32.112 21.6 32.136 ;
    END
  END b[210]
  PIN b[211]
    DIRECTION OUTPUT ;
    USE SIGNAL ;
    PORT
      LAYER M4 ;
        RECT  21.516 32.256 21.6 32.28 ;
    END
  END b[211]
  PIN b[212]
    DIRECTION OUTPUT ;
    USE SIGNAL ;
    PORT
      LAYER M4 ;
        RECT  21.516 32.4 21.6 32.424 ;
    END
  END b[212]
  PIN b[213]
    DIRECTION OUTPUT ;
    USE SIGNAL ;
    PORT
      LAYER M4 ;
        RECT  21.516 32.544 21.6 32.568 ;
    END
  END b[213]
  PIN b[214]
    DIRECTION OUTPUT ;
    USE SIGNAL ;
    PORT
      LAYER M4 ;
        RECT  21.516 32.688 21.6 32.712 ;
    END
  END b[214]
  PIN b[215]
    DIRECTION OUTPUT ;
    USE SIGNAL ;
    PORT
      LAYER M4 ;
        RECT  21.516 32.832 21.6 32.856 ;
    END
  END b[215]
  PIN b[216]
    DIRECTION OUTPUT ;
    USE SIGNAL ;
    PORT
      LAYER M4 ;
        RECT  21.516 32.976 21.6 33 ;
    END
  END b[216]
  PIN b[217]
    DIRECTION OUTPUT ;
    USE SIGNAL ;
    PORT
      LAYER M4 ;
        RECT  21.516 33.12 21.6 33.144 ;
    END
  END b[217]
  PIN b[218]
    DIRECTION OUTPUT ;
    USE SIGNAL ;
    PORT
      LAYER M4 ;
        RECT  21.516 33.264 21.6 33.288 ;
    END
  END b[218]
  PIN b[219]
    DIRECTION OUTPUT ;
    USE SIGNAL ;
    PORT
      LAYER M4 ;
        RECT  21.516 33.408 21.6 33.432 ;
    END
  END b[219]
  PIN b[21]
    DIRECTION OUTPUT ;
    USE SIGNAL ;
    PORT
      LAYER M4 ;
        RECT  21.516 3.744 21.6 3.768 ;
    END
  END b[21]
  PIN b[220]
    DIRECTION OUTPUT ;
    USE SIGNAL ;
    PORT
      LAYER M4 ;
        RECT  21.516 33.552 21.6 33.576 ;
    END
  END b[220]
  PIN b[221]
    DIRECTION OUTPUT ;
    USE SIGNAL ;
    PORT
      LAYER M4 ;
        RECT  21.516 33.696 21.6 33.72 ;
    END
  END b[221]
  PIN b[222]
    DIRECTION OUTPUT ;
    USE SIGNAL ;
    PORT
      LAYER M4 ;
        RECT  21.516 33.84 21.6 33.864 ;
    END
  END b[222]
  PIN b[223]
    DIRECTION OUTPUT ;
    USE SIGNAL ;
    PORT
      LAYER M4 ;
        RECT  21.516 33.984 21.6 34.008 ;
    END
  END b[223]
  PIN b[224]
    DIRECTION OUTPUT ;
    USE SIGNAL ;
    PORT
      LAYER M4 ;
        RECT  21.516 34.128 21.6 34.152 ;
    END
  END b[224]
  PIN b[225]
    DIRECTION OUTPUT ;
    USE SIGNAL ;
    PORT
      LAYER M4 ;
        RECT  21.516 34.272 21.6 34.296 ;
    END
  END b[225]
  PIN b[226]
    DIRECTION OUTPUT ;
    USE SIGNAL ;
    PORT
      LAYER M4 ;
        RECT  21.516 34.416 21.6 34.44 ;
    END
  END b[226]
  PIN b[227]
    DIRECTION OUTPUT ;
    USE SIGNAL ;
    PORT
      LAYER M4 ;
        RECT  21.516 34.56 21.6 34.584 ;
    END
  END b[227]
  PIN b[228]
    DIRECTION OUTPUT ;
    USE SIGNAL ;
    PORT
      LAYER M4 ;
        RECT  21.516 34.704 21.6 34.728 ;
    END
  END b[228]
  PIN b[229]
    DIRECTION OUTPUT ;
    USE SIGNAL ;
    PORT
      LAYER M4 ;
        RECT  21.516 34.848 21.6 34.872 ;
    END
  END b[229]
  PIN b[22]
    DIRECTION OUTPUT ;
    USE SIGNAL ;
    PORT
      LAYER M4 ;
        RECT  21.516 3.888 21.6 3.912 ;
    END
  END b[22]
  PIN b[230]
    DIRECTION OUTPUT ;
    USE SIGNAL ;
    PORT
      LAYER M4 ;
        RECT  21.516 34.992 21.6 35.016 ;
    END
  END b[230]
  PIN b[231]
    DIRECTION OUTPUT ;
    USE SIGNAL ;
    PORT
      LAYER M4 ;
        RECT  21.516 35.136 21.6 35.16 ;
    END
  END b[231]
  PIN b[232]
    DIRECTION OUTPUT ;
    USE SIGNAL ;
    PORT
      LAYER M4 ;
        RECT  21.516 35.28 21.6 35.304 ;
    END
  END b[232]
  PIN b[233]
    DIRECTION OUTPUT ;
    USE SIGNAL ;
    PORT
      LAYER M4 ;
        RECT  21.516 35.424 21.6 35.448 ;
    END
  END b[233]
  PIN b[234]
    DIRECTION OUTPUT ;
    USE SIGNAL ;
    PORT
      LAYER M4 ;
        RECT  21.516 35.568 21.6 35.592 ;
    END
  END b[234]
  PIN b[235]
    DIRECTION OUTPUT ;
    USE SIGNAL ;
    PORT
      LAYER M4 ;
        RECT  21.516 35.712 21.6 35.736 ;
    END
  END b[235]
  PIN b[236]
    DIRECTION OUTPUT ;
    USE SIGNAL ;
    PORT
      LAYER M4 ;
        RECT  21.516 35.856 21.6 35.88 ;
    END
  END b[236]
  PIN b[237]
    DIRECTION OUTPUT ;
    USE SIGNAL ;
    PORT
      LAYER M4 ;
        RECT  21.516 36 21.6 36.024 ;
    END
  END b[237]
  PIN b[238]
    DIRECTION OUTPUT ;
    USE SIGNAL ;
    PORT
      LAYER M4 ;
        RECT  21.516 36.144 21.6 36.168 ;
    END
  END b[238]
  PIN b[239]
    DIRECTION OUTPUT ;
    USE SIGNAL ;
    PORT
      LAYER M4 ;
        RECT  21.516 36.288 21.6 36.312 ;
    END
  END b[239]
  PIN b[23]
    DIRECTION OUTPUT ;
    USE SIGNAL ;
    PORT
      LAYER M4 ;
        RECT  21.516 4.032 21.6 4.056 ;
    END
  END b[23]
  PIN b[240]
    DIRECTION OUTPUT ;
    USE SIGNAL ;
    PORT
      LAYER M4 ;
        RECT  21.516 36.432 21.6 36.456 ;
    END
  END b[240]
  PIN b[241]
    DIRECTION OUTPUT ;
    USE SIGNAL ;
    PORT
      LAYER M4 ;
        RECT  21.516 36.576 21.6 36.6 ;
    END
  END b[241]
  PIN b[242]
    DIRECTION OUTPUT ;
    USE SIGNAL ;
    PORT
      LAYER M4 ;
        RECT  21.516 36.72 21.6 36.744 ;
    END
  END b[242]
  PIN b[243]
    DIRECTION OUTPUT ;
    USE SIGNAL ;
    PORT
      LAYER M4 ;
        RECT  21.516 36.864 21.6 36.888 ;
    END
  END b[243]
  PIN b[244]
    DIRECTION OUTPUT ;
    USE SIGNAL ;
    PORT
      LAYER M4 ;
        RECT  21.516 37.008 21.6 37.032 ;
    END
  END b[244]
  PIN b[245]
    DIRECTION OUTPUT ;
    USE SIGNAL ;
    PORT
      LAYER M4 ;
        RECT  21.516 37.152 21.6 37.176 ;
    END
  END b[245]
  PIN b[246]
    DIRECTION OUTPUT ;
    USE SIGNAL ;
    PORT
      LAYER M4 ;
        RECT  21.516 37.296 21.6 37.32 ;
    END
  END b[246]
  PIN b[247]
    DIRECTION OUTPUT ;
    USE SIGNAL ;
    PORT
      LAYER M4 ;
        RECT  21.516 37.44 21.6 37.464 ;
    END
  END b[247]
  PIN b[248]
    DIRECTION OUTPUT ;
    USE SIGNAL ;
    PORT
      LAYER M4 ;
        RECT  21.516 37.584 21.6 37.608 ;
    END
  END b[248]
  PIN b[249]
    DIRECTION OUTPUT ;
    USE SIGNAL ;
    PORT
      LAYER M4 ;
        RECT  21.516 37.728 21.6 37.752 ;
    END
  END b[249]
  PIN b[24]
    DIRECTION OUTPUT ;
    USE SIGNAL ;
    PORT
      LAYER M4 ;
        RECT  21.516 4.176 21.6 4.2 ;
    END
  END b[24]
  PIN b[250]
    DIRECTION OUTPUT ;
    USE SIGNAL ;
    PORT
      LAYER M4 ;
        RECT  21.516 37.872 21.6 37.896 ;
    END
  END b[250]
  PIN b[251]
    DIRECTION OUTPUT ;
    USE SIGNAL ;
    PORT
      LAYER M4 ;
        RECT  21.516 38.016 21.6 38.04 ;
    END
  END b[251]
  PIN b[252]
    DIRECTION OUTPUT ;
    USE SIGNAL ;
    PORT
      LAYER M4 ;
        RECT  21.516 38.16 21.6 38.184 ;
    END
  END b[252]
  PIN b[253]
    DIRECTION OUTPUT ;
    USE SIGNAL ;
    PORT
      LAYER M4 ;
        RECT  21.516 38.304 21.6 38.328 ;
    END
  END b[253]
  PIN b[254]
    DIRECTION OUTPUT ;
    USE SIGNAL ;
    PORT
      LAYER M4 ;
        RECT  21.516 38.448 21.6 38.472 ;
    END
  END b[254]
  PIN b[255]
    DIRECTION OUTPUT ;
    USE SIGNAL ;
    PORT
      LAYER M4 ;
        RECT  21.516 38.592 21.6 38.616 ;
    END
  END b[255]
  PIN b[256]
    DIRECTION OUTPUT ;
    USE SIGNAL ;
    PORT
      LAYER M4 ;
        RECT  21.516 38.736 21.6 38.76 ;
    END
  END b[256]
  PIN b[257]
    DIRECTION OUTPUT ;
    USE SIGNAL ;
    PORT
      LAYER M4 ;
        RECT  21.516 38.88 21.6 38.904 ;
    END
  END b[257]
  PIN b[258]
    DIRECTION OUTPUT ;
    USE SIGNAL ;
    PORT
      LAYER M4 ;
        RECT  21.516 39.024 21.6 39.048 ;
    END
  END b[258]
  PIN b[259]
    DIRECTION OUTPUT ;
    USE SIGNAL ;
    PORT
      LAYER M4 ;
        RECT  21.516 39.168 21.6 39.192 ;
    END
  END b[259]
  PIN b[25]
    DIRECTION OUTPUT ;
    USE SIGNAL ;
    PORT
      LAYER M4 ;
        RECT  21.516 4.32 21.6 4.344 ;
    END
  END b[25]
  PIN b[260]
    DIRECTION OUTPUT ;
    USE SIGNAL ;
    PORT
      LAYER M4 ;
        RECT  21.516 39.312 21.6 39.336 ;
    END
  END b[260]
  PIN b[261]
    DIRECTION OUTPUT ;
    USE SIGNAL ;
    PORT
      LAYER M4 ;
        RECT  21.516 39.456 21.6 39.48 ;
    END
  END b[261]
  PIN b[262]
    DIRECTION OUTPUT ;
    USE SIGNAL ;
    PORT
      LAYER M4 ;
        RECT  21.516 39.6 21.6 39.624 ;
    END
  END b[262]
  PIN b[263]
    DIRECTION OUTPUT ;
    USE SIGNAL ;
    PORT
      LAYER M4 ;
        RECT  21.516 39.744 21.6 39.768 ;
    END
  END b[263]
  PIN b[264]
    DIRECTION OUTPUT ;
    USE SIGNAL ;
    PORT
      LAYER M4 ;
        RECT  21.516 39.888 21.6 39.912 ;
    END
  END b[264]
  PIN b[265]
    DIRECTION OUTPUT ;
    USE SIGNAL ;
    PORT
      LAYER M4 ;
        RECT  21.516 40.032 21.6 40.056 ;
    END
  END b[265]
  PIN b[266]
    DIRECTION OUTPUT ;
    USE SIGNAL ;
    PORT
      LAYER M4 ;
        RECT  21.516 40.176 21.6 40.2 ;
    END
  END b[266]
  PIN b[267]
    DIRECTION OUTPUT ;
    USE SIGNAL ;
    PORT
      LAYER M4 ;
        RECT  21.516 40.32 21.6 40.344 ;
    END
  END b[267]
  PIN b[268]
    DIRECTION OUTPUT ;
    USE SIGNAL ;
    PORT
      LAYER M4 ;
        RECT  21.516 40.464 21.6 40.488 ;
    END
  END b[268]
  PIN b[269]
    DIRECTION OUTPUT ;
    USE SIGNAL ;
    PORT
      LAYER M4 ;
        RECT  21.516 40.608 21.6 40.632 ;
    END
  END b[269]
  PIN b[26]
    DIRECTION OUTPUT ;
    USE SIGNAL ;
    PORT
      LAYER M4 ;
        RECT  21.516 4.464 21.6 4.488 ;
    END
  END b[26]
  PIN b[270]
    DIRECTION OUTPUT ;
    USE SIGNAL ;
    PORT
      LAYER M4 ;
        RECT  21.516 40.752 21.6 40.776 ;
    END
  END b[270]
  PIN b[271]
    DIRECTION OUTPUT ;
    USE SIGNAL ;
    PORT
      LAYER M4 ;
        RECT  21.516 40.896 21.6 40.92 ;
    END
  END b[271]
  PIN b[272]
    DIRECTION OUTPUT ;
    USE SIGNAL ;
    PORT
      LAYER M4 ;
        RECT  21.516 41.04 21.6 41.064 ;
    END
  END b[272]
  PIN b[273]
    DIRECTION OUTPUT ;
    USE SIGNAL ;
    PORT
      LAYER M4 ;
        RECT  21.516 41.184 21.6 41.208 ;
    END
  END b[273]
  PIN b[274]
    DIRECTION OUTPUT ;
    USE SIGNAL ;
    PORT
      LAYER M4 ;
        RECT  21.516 41.328 21.6 41.352 ;
    END
  END b[274]
  PIN b[275]
    DIRECTION OUTPUT ;
    USE SIGNAL ;
    PORT
      LAYER M4 ;
        RECT  21.516 41.472 21.6 41.496 ;
    END
  END b[275]
  PIN b[276]
    DIRECTION OUTPUT ;
    USE SIGNAL ;
    PORT
      LAYER M4 ;
        RECT  21.516 41.616 21.6 41.64 ;
    END
  END b[276]
  PIN b[277]
    DIRECTION OUTPUT ;
    USE SIGNAL ;
    PORT
      LAYER M4 ;
        RECT  21.516 41.76 21.6 41.784 ;
    END
  END b[277]
  PIN b[278]
    DIRECTION OUTPUT ;
    USE SIGNAL ;
    PORT
      LAYER M4 ;
        RECT  21.516 41.904 21.6 41.928 ;
    END
  END b[278]
  PIN b[279]
    DIRECTION OUTPUT ;
    USE SIGNAL ;
    PORT
      LAYER M4 ;
        RECT  21.516 42.048 21.6 42.072 ;
    END
  END b[279]
  PIN b[27]
    DIRECTION OUTPUT ;
    USE SIGNAL ;
    PORT
      LAYER M4 ;
        RECT  21.516 4.608 21.6 4.632 ;
    END
  END b[27]
  PIN b[280]
    DIRECTION OUTPUT ;
    USE SIGNAL ;
    PORT
      LAYER M4 ;
        RECT  21.516 42.192 21.6 42.216 ;
    END
  END b[280]
  PIN b[281]
    DIRECTION OUTPUT ;
    USE SIGNAL ;
    PORT
      LAYER M4 ;
        RECT  21.516 42.336 21.6 42.36 ;
    END
  END b[281]
  PIN b[282]
    DIRECTION OUTPUT ;
    USE SIGNAL ;
    PORT
      LAYER M4 ;
        RECT  21.516 42.48 21.6 42.504 ;
    END
  END b[282]
  PIN b[283]
    DIRECTION OUTPUT ;
    USE SIGNAL ;
    PORT
      LAYER M4 ;
        RECT  21.516 42.624 21.6 42.648 ;
    END
  END b[283]
  PIN b[284]
    DIRECTION OUTPUT ;
    USE SIGNAL ;
    PORT
      LAYER M4 ;
        RECT  21.516 42.768 21.6 42.792 ;
    END
  END b[284]
  PIN b[285]
    DIRECTION OUTPUT ;
    USE SIGNAL ;
    PORT
      LAYER M4 ;
        RECT  21.516 42.912 21.6 42.936 ;
    END
  END b[285]
  PIN b[286]
    DIRECTION OUTPUT ;
    USE SIGNAL ;
    PORT
      LAYER M4 ;
        RECT  21.516 43.056 21.6 43.08 ;
    END
  END b[286]
  PIN b[287]
    DIRECTION OUTPUT ;
    USE SIGNAL ;
    PORT
      LAYER M4 ;
        RECT  21.516 43.2 21.6 43.224 ;
    END
  END b[287]
  PIN b[288]
    DIRECTION OUTPUT ;
    USE SIGNAL ;
    PORT
      LAYER M4 ;
        RECT  21.516 28.368 21.6 28.392 ;
    END
  END b[288]
  PIN b[289]
    DIRECTION OUTPUT ;
    USE SIGNAL ;
    PORT
      LAYER M4 ;
        RECT  21.516 28.512 21.6 28.536 ;
    END
  END b[289]
  PIN b[28]
    DIRECTION OUTPUT ;
    USE SIGNAL ;
    PORT
      LAYER M4 ;
        RECT  21.516 4.752 21.6 4.776 ;
    END
  END b[28]
  PIN b[290]
    DIRECTION OUTPUT ;
    USE SIGNAL ;
    PORT
      LAYER M4 ;
        RECT  21.516 28.656 21.6 28.68 ;
    END
  END b[290]
  PIN b[291]
    DIRECTION OUTPUT ;
    USE SIGNAL ;
    PORT
      LAYER M4 ;
        RECT  21.516 28.8 21.6 28.824 ;
    END
  END b[291]
  PIN b[292]
    DIRECTION OUTPUT ;
    USE SIGNAL ;
    PORT
      LAYER M4 ;
        RECT  21.516 28.944 21.6 28.968 ;
    END
  END b[292]
  PIN b[293]
    DIRECTION OUTPUT ;
    USE SIGNAL ;
    PORT
      LAYER M4 ;
        RECT  21.516 29.088 21.6 29.112 ;
    END
  END b[293]
  PIN b[294]
    DIRECTION OUTPUT ;
    USE SIGNAL ;
    PORT
      LAYER M4 ;
        RECT  21.516 29.232 21.6 29.256 ;
    END
  END b[294]
  PIN b[295]
    DIRECTION OUTPUT ;
    USE SIGNAL ;
    PORT
      LAYER M4 ;
        RECT  21.516 29.376 21.6 29.4 ;
    END
  END b[295]
  PIN b[29]
    DIRECTION OUTPUT ;
    USE SIGNAL ;
    PORT
      LAYER M4 ;
        RECT  21.516 4.896 21.6 4.92 ;
    END
  END b[29]
  PIN b[2]
    DIRECTION OUTPUT ;
    USE SIGNAL ;
    PORT
      LAYER M4 ;
        RECT  21.516 1.008 21.6 1.032 ;
    END
  END b[2]
  PIN b[30]
    DIRECTION OUTPUT ;
    USE SIGNAL ;
    PORT
      LAYER M4 ;
        RECT  21.516 5.04 21.6 5.064 ;
    END
  END b[30]
  PIN b[31]
    DIRECTION OUTPUT ;
    USE SIGNAL ;
    PORT
      LAYER M4 ;
        RECT  21.516 5.184 21.6 5.208 ;
    END
  END b[31]
  PIN b[32]
    DIRECTION OUTPUT ;
    USE SIGNAL ;
    PORT
      LAYER M4 ;
        RECT  21.516 5.328 21.6 5.352 ;
    END
  END b[32]
  PIN b[33]
    DIRECTION OUTPUT ;
    USE SIGNAL ;
    PORT
      LAYER M4 ;
        RECT  21.516 5.472 21.6 5.496 ;
    END
  END b[33]
  PIN b[34]
    DIRECTION OUTPUT ;
    USE SIGNAL ;
    PORT
      LAYER M4 ;
        RECT  21.516 5.616 21.6 5.64 ;
    END
  END b[34]
  PIN b[35]
    DIRECTION OUTPUT ;
    USE SIGNAL ;
    PORT
      LAYER M4 ;
        RECT  21.516 5.76 21.6 5.784 ;
    END
  END b[35]
  PIN b[36]
    DIRECTION OUTPUT ;
    USE SIGNAL ;
    PORT
      LAYER M4 ;
        RECT  21.516 5.904 21.6 5.928 ;
    END
  END b[36]
  PIN b[37]
    DIRECTION OUTPUT ;
    USE SIGNAL ;
    PORT
      LAYER M4 ;
        RECT  21.516 6.048 21.6 6.072 ;
    END
  END b[37]
  PIN b[38]
    DIRECTION OUTPUT ;
    USE SIGNAL ;
    PORT
      LAYER M4 ;
        RECT  21.516 6.192 21.6 6.216 ;
    END
  END b[38]
  PIN b[39]
    DIRECTION OUTPUT ;
    USE SIGNAL ;
    PORT
      LAYER M4 ;
        RECT  21.516 6.336 21.6 6.36 ;
    END
  END b[39]
  PIN b[3]
    DIRECTION OUTPUT ;
    USE SIGNAL ;
    PORT
      LAYER M4 ;
        RECT  21.516 1.152 21.6 1.176 ;
    END
  END b[3]
  PIN b[40]
    DIRECTION OUTPUT ;
    USE SIGNAL ;
    PORT
      LAYER M4 ;
        RECT  21.516 6.48 21.6 6.504 ;
    END
  END b[40]
  PIN b[41]
    DIRECTION OUTPUT ;
    USE SIGNAL ;
    PORT
      LAYER M4 ;
        RECT  21.516 6.624 21.6 6.648 ;
    END
  END b[41]
  PIN b[42]
    DIRECTION OUTPUT ;
    USE SIGNAL ;
    PORT
      LAYER M4 ;
        RECT  21.516 6.768 21.6 6.792 ;
    END
  END b[42]
  PIN b[43]
    DIRECTION OUTPUT ;
    USE SIGNAL ;
    PORT
      LAYER M4 ;
        RECT  21.516 6.912 21.6 6.936 ;
    END
  END b[43]
  PIN b[44]
    DIRECTION OUTPUT ;
    USE SIGNAL ;
    PORT
      LAYER M4 ;
        RECT  21.516 7.056 21.6 7.08 ;
    END
  END b[44]
  PIN b[45]
    DIRECTION OUTPUT ;
    USE SIGNAL ;
    PORT
      LAYER M4 ;
        RECT  21.516 7.2 21.6 7.224 ;
    END
  END b[45]
  PIN b[46]
    DIRECTION OUTPUT ;
    USE SIGNAL ;
    PORT
      LAYER M4 ;
        RECT  21.516 7.344 21.6 7.368 ;
    END
  END b[46]
  PIN b[47]
    DIRECTION OUTPUT ;
    USE SIGNAL ;
    PORT
      LAYER M4 ;
        RECT  21.516 7.488 21.6 7.512 ;
    END
  END b[47]
  PIN b[48]
    DIRECTION OUTPUT ;
    USE SIGNAL ;
    PORT
      LAYER M4 ;
        RECT  21.516 7.632 21.6 7.656 ;
    END
  END b[48]
  PIN b[49]
    DIRECTION OUTPUT ;
    USE SIGNAL ;
    PORT
      LAYER M4 ;
        RECT  21.516 7.776 21.6 7.8 ;
    END
  END b[49]
  PIN b[4]
    DIRECTION OUTPUT ;
    USE SIGNAL ;
    PORT
      LAYER M4 ;
        RECT  21.516 1.296 21.6 1.32 ;
    END
  END b[4]
  PIN b[50]
    DIRECTION OUTPUT ;
    USE SIGNAL ;
    PORT
      LAYER M4 ;
        RECT  21.516 7.92 21.6 7.944 ;
    END
  END b[50]
  PIN b[51]
    DIRECTION OUTPUT ;
    USE SIGNAL ;
    PORT
      LAYER M4 ;
        RECT  21.516 8.064 21.6 8.088 ;
    END
  END b[51]
  PIN b[52]
    DIRECTION OUTPUT ;
    USE SIGNAL ;
    PORT
      LAYER M4 ;
        RECT  21.516 8.208 21.6 8.232 ;
    END
  END b[52]
  PIN b[53]
    DIRECTION OUTPUT ;
    USE SIGNAL ;
    PORT
      LAYER M4 ;
        RECT  21.516 8.352 21.6 8.376 ;
    END
  END b[53]
  PIN b[54]
    DIRECTION OUTPUT ;
    USE SIGNAL ;
    PORT
      LAYER M4 ;
        RECT  21.516 8.496 21.6 8.52 ;
    END
  END b[54]
  PIN b[55]
    DIRECTION OUTPUT ;
    USE SIGNAL ;
    PORT
      LAYER M4 ;
        RECT  21.516 8.64 21.6 8.664 ;
    END
  END b[55]
  PIN b[56]
    DIRECTION OUTPUT ;
    USE SIGNAL ;
    PORT
      LAYER M4 ;
        RECT  21.516 8.784 21.6 8.808 ;
    END
  END b[56]
  PIN b[57]
    DIRECTION OUTPUT ;
    USE SIGNAL ;
    PORT
      LAYER M4 ;
        RECT  21.516 8.928 21.6 8.952 ;
    END
  END b[57]
  PIN b[58]
    DIRECTION OUTPUT ;
    USE SIGNAL ;
    PORT
      LAYER M4 ;
        RECT  21.516 9.072 21.6 9.096 ;
    END
  END b[58]
  PIN b[59]
    DIRECTION OUTPUT ;
    USE SIGNAL ;
    PORT
      LAYER M4 ;
        RECT  21.516 9.216 21.6 9.24 ;
    END
  END b[59]
  PIN b[5]
    DIRECTION OUTPUT ;
    USE SIGNAL ;
    PORT
      LAYER M4 ;
        RECT  21.516 1.44 21.6 1.464 ;
    END
  END b[5]
  PIN b[60]
    DIRECTION OUTPUT ;
    USE SIGNAL ;
    PORT
      LAYER M4 ;
        RECT  21.516 9.36 21.6 9.384 ;
    END
  END b[60]
  PIN b[61]
    DIRECTION OUTPUT ;
    USE SIGNAL ;
    PORT
      LAYER M4 ;
        RECT  21.516 9.504 21.6 9.528 ;
    END
  END b[61]
  PIN b[62]
    DIRECTION OUTPUT ;
    USE SIGNAL ;
    PORT
      LAYER M4 ;
        RECT  21.516 9.648 21.6 9.672 ;
    END
  END b[62]
  PIN b[63]
    DIRECTION OUTPUT ;
    USE SIGNAL ;
    PORT
      LAYER M4 ;
        RECT  21.516 9.792 21.6 9.816 ;
    END
  END b[63]
  PIN b[64]
    DIRECTION OUTPUT ;
    USE SIGNAL ;
    PORT
      LAYER M4 ;
        RECT  21.516 19.152 21.6 19.176 ;
    END
  END b[64]
  PIN b[65]
    DIRECTION OUTPUT ;
    USE SIGNAL ;
    PORT
      LAYER M4 ;
        RECT  21.516 19.296 21.6 19.32 ;
    END
  END b[65]
  PIN b[66]
    DIRECTION OUTPUT ;
    USE SIGNAL ;
    PORT
      LAYER M4 ;
        RECT  21.516 19.44 21.6 19.464 ;
    END
  END b[66]
  PIN b[67]
    DIRECTION OUTPUT ;
    USE SIGNAL ;
    PORT
      LAYER M4 ;
        RECT  21.516 19.584 21.6 19.608 ;
    END
  END b[67]
  PIN b[68]
    DIRECTION OUTPUT ;
    USE SIGNAL ;
    PORT
      LAYER M4 ;
        RECT  21.516 19.728 21.6 19.752 ;
    END
  END b[68]
  PIN b[69]
    DIRECTION OUTPUT ;
    USE SIGNAL ;
    PORT
      LAYER M4 ;
        RECT  21.516 19.872 21.6 19.896 ;
    END
  END b[69]
  PIN b[6]
    DIRECTION OUTPUT ;
    USE SIGNAL ;
    PORT
      LAYER M4 ;
        RECT  21.516 1.584 21.6 1.608 ;
    END
  END b[6]
  PIN b[70]
    DIRECTION OUTPUT ;
    USE SIGNAL ;
    PORT
      LAYER M4 ;
        RECT  21.516 20.016 21.6 20.04 ;
    END
  END b[70]
  PIN b[71]
    DIRECTION OUTPUT ;
    USE SIGNAL ;
    PORT
      LAYER M4 ;
        RECT  21.516 20.16 21.6 20.184 ;
    END
  END b[71]
  PIN b[72]
    DIRECTION OUTPUT ;
    USE SIGNAL ;
    PORT
      LAYER M4 ;
        RECT  21.516 20.304 21.6 20.328 ;
    END
  END b[72]
  PIN b[73]
    DIRECTION OUTPUT ;
    USE SIGNAL ;
    PORT
      LAYER M4 ;
        RECT  21.516 20.448 21.6 20.472 ;
    END
  END b[73]
  PIN b[74]
    DIRECTION OUTPUT ;
    USE SIGNAL ;
    PORT
      LAYER M4 ;
        RECT  21.516 20.592 21.6 20.616 ;
    END
  END b[74]
  PIN b[75]
    DIRECTION OUTPUT ;
    USE SIGNAL ;
    PORT
      LAYER M4 ;
        RECT  21.516 20.736 21.6 20.76 ;
    END
  END b[75]
  PIN b[76]
    DIRECTION OUTPUT ;
    USE SIGNAL ;
    PORT
      LAYER M4 ;
        RECT  21.516 20.88 21.6 20.904 ;
    END
  END b[76]
  PIN b[77]
    DIRECTION OUTPUT ;
    USE SIGNAL ;
    PORT
      LAYER M4 ;
        RECT  21.516 21.024 21.6 21.048 ;
    END
  END b[77]
  PIN b[78]
    DIRECTION OUTPUT ;
    USE SIGNAL ;
    PORT
      LAYER M4 ;
        RECT  21.516 21.168 21.6 21.192 ;
    END
  END b[78]
  PIN b[79]
    DIRECTION OUTPUT ;
    USE SIGNAL ;
    PORT
      LAYER M4 ;
        RECT  21.516 21.312 21.6 21.336 ;
    END
  END b[79]
  PIN b[7]
    DIRECTION OUTPUT ;
    USE SIGNAL ;
    PORT
      LAYER M4 ;
        RECT  21.516 1.728 21.6 1.752 ;
    END
  END b[7]
  PIN b[80]
    DIRECTION OUTPUT ;
    USE SIGNAL ;
    PORT
      LAYER M4 ;
        RECT  21.516 21.456 21.6 21.48 ;
    END
  END b[80]
  PIN b[81]
    DIRECTION OUTPUT ;
    USE SIGNAL ;
    PORT
      LAYER M4 ;
        RECT  21.516 21.6 21.6 21.624 ;
    END
  END b[81]
  PIN b[82]
    DIRECTION OUTPUT ;
    USE SIGNAL ;
    PORT
      LAYER M4 ;
        RECT  21.516 21.744 21.6 21.768 ;
    END
  END b[82]
  PIN b[83]
    DIRECTION OUTPUT ;
    USE SIGNAL ;
    PORT
      LAYER M4 ;
        RECT  21.516 21.888 21.6 21.912 ;
    END
  END b[83]
  PIN b[84]
    DIRECTION OUTPUT ;
    USE SIGNAL ;
    PORT
      LAYER M4 ;
        RECT  21.516 22.032 21.6 22.056 ;
    END
  END b[84]
  PIN b[85]
    DIRECTION OUTPUT ;
    USE SIGNAL ;
    PORT
      LAYER M4 ;
        RECT  21.516 22.176 21.6 22.2 ;
    END
  END b[85]
  PIN b[86]
    DIRECTION OUTPUT ;
    USE SIGNAL ;
    PORT
      LAYER M4 ;
        RECT  21.516 22.32 21.6 22.344 ;
    END
  END b[86]
  PIN b[87]
    DIRECTION OUTPUT ;
    USE SIGNAL ;
    PORT
      LAYER M4 ;
        RECT  21.516 22.464 21.6 22.488 ;
    END
  END b[87]
  PIN b[88]
    DIRECTION OUTPUT ;
    USE SIGNAL ;
    PORT
      LAYER M4 ;
        RECT  21.516 22.608 21.6 22.632 ;
    END
  END b[88]
  PIN b[89]
    DIRECTION OUTPUT ;
    USE SIGNAL ;
    PORT
      LAYER M4 ;
        RECT  21.516 22.752 21.6 22.776 ;
    END
  END b[89]
  PIN b[8]
    DIRECTION OUTPUT ;
    USE SIGNAL ;
    PORT
      LAYER M4 ;
        RECT  21.516 1.872 21.6 1.896 ;
    END
  END b[8]
  PIN b[90]
    DIRECTION OUTPUT ;
    USE SIGNAL ;
    PORT
      LAYER M4 ;
        RECT  21.516 22.896 21.6 22.92 ;
    END
  END b[90]
  PIN b[91]
    DIRECTION OUTPUT ;
    USE SIGNAL ;
    PORT
      LAYER M4 ;
        RECT  21.516 23.04 21.6 23.064 ;
    END
  END b[91]
  PIN b[92]
    DIRECTION OUTPUT ;
    USE SIGNAL ;
    PORT
      LAYER M4 ;
        RECT  21.516 23.184 21.6 23.208 ;
    END
  END b[92]
  PIN b[93]
    DIRECTION OUTPUT ;
    USE SIGNAL ;
    PORT
      LAYER M4 ;
        RECT  21.516 23.328 21.6 23.352 ;
    END
  END b[93]
  PIN b[94]
    DIRECTION OUTPUT ;
    USE SIGNAL ;
    PORT
      LAYER M4 ;
        RECT  21.516 23.472 21.6 23.496 ;
    END
  END b[94]
  PIN b[95]
    DIRECTION OUTPUT ;
    USE SIGNAL ;
    PORT
      LAYER M4 ;
        RECT  21.516 23.616 21.6 23.64 ;
    END
  END b[95]
  PIN b[96]
    DIRECTION OUTPUT ;
    USE SIGNAL ;
    PORT
      LAYER M4 ;
        RECT  21.516 9.936 21.6 9.96 ;
    END
  END b[96]
  PIN b[97]
    DIRECTION OUTPUT ;
    USE SIGNAL ;
    PORT
      LAYER M4 ;
        RECT  21.516 10.08 21.6 10.104 ;
    END
  END b[97]
  PIN b[98]
    DIRECTION OUTPUT ;
    USE SIGNAL ;
    PORT
      LAYER M4 ;
        RECT  21.516 10.224 21.6 10.248 ;
    END
  END b[98]
  PIN b[99]
    DIRECTION OUTPUT ;
    USE SIGNAL ;
    PORT
      LAYER M4 ;
        RECT  21.516 10.368 21.6 10.392 ;
    END
  END b[99]
  PIN b[9]
    DIRECTION OUTPUT ;
    USE SIGNAL ;
    PORT
      LAYER M4 ;
        RECT  21.516 2.016 21.6 2.04 ;
    END
  END b[9]
  PIN ck
    DIRECTION INPUT ;
    USE SIGNAL ;
    PORT
      LAYER M5 ;
        RECT  7.92 0 7.944 0.084 ;
    END
  END ck
  PIN ck_o
    DIRECTION OUTPUT ;
    USE SIGNAL ;
    PORT
      LAYER M3 ;
        RECT  10.908 47.483 10.926 47.52 ;
    END
  END ck_o
  PIN eb
    DIRECTION OUTPUT ;
    USE SIGNAL ;
    PORT
      LAYER M3 ;
        RECT  11.016 47.483 11.034 47.52 ;
    END
  END eb
  PIN en
    DIRECTION INPUT ;
    USE SIGNAL ;
    PORT
      LAYER M5 ;
        RECT  8.064 0 8.088 0.084 ;
    END
  END en
  PIN VDD
    DIRECTION INOUT ;
    USE POWER ;
    PORT
      LAYER M5 ;
        RECT  18.792 2.151 18.912 45.369 ;
        RECT  16.092 2.151 16.212 45.369 ;
        RECT  13.392 2.151 13.512 45.369 ;
        RECT  10.692 2.151 10.812 45.369 ;
        RECT  7.992 2.151 8.112 45.369 ;
        RECT  5.292 2.151 5.412 45.369 ;
        RECT  2.592 2.151 2.712 45.369 ;
    END
  END VDD
  PIN VSS
    DIRECTION INOUT ;
    USE GROUND ;
    PORT
      LAYER M5 ;
        RECT  18.6 2.137 18.72 45.383 ;
        RECT  15.9 2.137 16.02 45.383 ;
        RECT  13.2 2.137 13.32 45.383 ;
        RECT  10.5 2.137 10.62 45.383 ;
        RECT  7.8 2.137 7.92 45.383 ;
        RECT  5.1 2.137 5.22 45.383 ;
        RECT  2.4 2.137 2.52 45.383 ;
    END
  END VSS
  OBS
    LAYER RVTN ;
     RECT  2.16 2.16 19.44 2.295 ;
     RECT  2.16 2.565 19.44 2.835 ;
     RECT  2.16 3.105 19.44 3.375 ;
     RECT  2.16 3.645 19.44 3.915 ;
     RECT  2.16 4.185 19.44 4.455 ;
     RECT  2.16 4.725 19.44 4.995 ;
     RECT  2.16 5.265 19.44 5.535 ;
     RECT  2.16 5.805 19.44 6.075 ;
     RECT  2.16 6.345 19.44 6.615 ;
     RECT  2.16 6.885 19.44 7.155 ;
     RECT  2.16 7.425 19.44 7.695 ;
     RECT  2.16 7.965 19.44 8.235 ;
     RECT  2.16 8.505 19.44 8.775 ;
     RECT  2.16 9.045 19.44 9.315 ;
     RECT  2.16 9.585 19.44 9.855 ;
     RECT  2.16 10.125 19.44 10.395 ;
     RECT  2.16 10.665 19.44 10.935 ;
     RECT  2.16 11.205 19.44 11.475 ;
     RECT  2.16 11.745 19.44 12.015 ;
     RECT  2.16 12.285 19.44 12.555 ;
     RECT  2.16 12.825 19.44 13.095 ;
     RECT  2.16 13.365 19.44 13.635 ;
     RECT  2.16 13.905 19.44 14.175 ;
     RECT  2.16 14.445 19.44 14.715 ;
     RECT  2.16 14.985 19.44 15.255 ;
     RECT  2.16 15.525 19.44 15.795 ;
     RECT  2.16 16.065 19.44 16.335 ;
     RECT  2.16 16.605 19.44 16.875 ;
     RECT  2.16 17.145 19.44 17.415 ;
     RECT  2.16 17.685 19.44 17.955 ;
     RECT  2.16 18.225 19.44 18.495 ;
     RECT  2.16 18.765 19.44 19.035 ;
     RECT  2.16 19.305 19.44 19.575 ;
     RECT  2.16 19.845 19.44 20.115 ;
     RECT  2.16 20.385 19.44 20.655 ;
     RECT  2.16 20.925 19.44 21.195 ;
     RECT  2.16 21.465 19.44 21.735 ;
     RECT  2.16 22.005 19.44 22.275 ;
     RECT  2.16 22.545 19.44 22.815 ;
     RECT  2.16 23.085 19.44 23.355 ;
     RECT  2.16 23.625 19.44 23.895 ;
     RECT  2.16 24.165 19.44 24.435 ;
     RECT  2.16 24.705 19.44 24.975 ;
     RECT  2.16 25.245 19.44 25.515 ;
     RECT  2.16 25.785 19.44 26.055 ;
     RECT  2.16 26.325 19.44 26.595 ;
     RECT  2.16 26.865 19.44 27.135 ;
     RECT  2.16 27.405 19.44 27.675 ;
     RECT  2.16 27.945 19.44 28.215 ;
     RECT  2.16 28.485 19.44 28.755 ;
     RECT  2.16 29.025 19.44 29.295 ;
     RECT  2.16 29.565 19.44 29.835 ;
     RECT  2.16 30.105 19.44 30.375 ;
     RECT  2.16 30.645 19.44 30.915 ;
     RECT  2.16 31.185 19.44 31.455 ;
     RECT  2.16 31.725 19.44 31.995 ;
     RECT  2.16 32.265 19.44 32.535 ;
     RECT  2.16 32.805 19.44 33.075 ;
     RECT  2.16 33.345 19.44 33.615 ;
     RECT  2.16 33.885 19.44 34.155 ;
     RECT  2.16 34.425 19.44 34.695 ;
     RECT  2.16 34.965 19.44 35.235 ;
     RECT  2.16 35.505 19.44 35.775 ;
     RECT  2.16 36.045 19.44 36.315 ;
     RECT  2.16 36.585 19.44 36.855 ;
     RECT  2.16 37.125 19.44 37.395 ;
     RECT  2.16 37.665 19.44 37.935 ;
     RECT  2.16 38.205 19.44 38.475 ;
     RECT  2.16 38.745 19.44 39.015 ;
     RECT  2.16 39.285 19.44 39.555 ;
     RECT  2.16 39.825 19.44 40.095 ;
     RECT  2.16 40.365 19.44 40.635 ;
     RECT  2.16 40.905 19.44 41.175 ;
     RECT  2.16 41.445 19.44 41.715 ;
     RECT  2.16 41.985 19.44 42.255 ;
     RECT  2.16 42.525 19.44 42.795 ;
     RECT  2.16 43.065 19.44 43.335 ;
     RECT  2.16 43.605 19.44 43.875 ;
     RECT  2.16 44.145 19.44 44.415 ;
     RECT  2.16 44.685 19.44 44.955 ;
     RECT  2.16 45.225 19.44 45.36 ;
    LAYER RVTP ;
     RECT  2.16 2.295 19.44 2.565 ;
     RECT  2.16 2.835 19.44 3.105 ;
     RECT  2.16 3.375 19.44 3.645 ;
     RECT  2.16 3.915 19.44 4.185 ;
     RECT  2.16 4.455 19.44 4.725 ;
     RECT  2.16 4.995 19.44 5.265 ;
     RECT  2.16 5.535 19.44 5.805 ;
     RECT  2.16 6.075 19.44 6.345 ;
     RECT  2.16 6.615 19.44 6.885 ;
     RECT  2.16 7.155 19.44 7.425 ;
     RECT  2.16 7.695 19.44 7.965 ;
     RECT  2.16 8.235 19.44 8.505 ;
     RECT  2.16 8.775 19.44 9.045 ;
     RECT  2.16 9.315 19.44 9.585 ;
     RECT  2.16 9.855 19.44 10.125 ;
     RECT  2.16 10.395 19.44 10.665 ;
     RECT  2.16 10.935 19.44 11.205 ;
     RECT  2.16 11.475 19.44 11.745 ;
     RECT  2.16 12.015 19.44 12.285 ;
     RECT  2.16 12.555 19.44 12.825 ;
     RECT  2.16 13.095 19.44 13.365 ;
     RECT  2.16 13.635 19.44 13.905 ;
     RECT  2.16 14.175 19.44 14.445 ;
     RECT  2.16 14.715 19.44 14.985 ;
     RECT  2.16 15.255 19.44 15.525 ;
     RECT  2.16 15.795 19.44 16.065 ;
     RECT  2.16 16.335 19.44 16.605 ;
     RECT  2.16 16.875 19.44 17.145 ;
     RECT  2.16 17.415 19.44 17.685 ;
     RECT  2.16 17.955 19.44 18.225 ;
     RECT  2.16 18.495 19.44 18.765 ;
     RECT  2.16 19.035 19.44 19.305 ;
     RECT  2.16 19.575 19.44 19.845 ;
     RECT  2.16 20.115 19.44 20.385 ;
     RECT  2.16 20.655 19.44 20.925 ;
     RECT  2.16 21.195 19.44 21.465 ;
     RECT  2.16 21.735 19.44 22.005 ;
     RECT  2.16 22.275 19.44 22.545 ;
     RECT  2.16 22.815 19.44 23.085 ;
     RECT  2.16 23.355 19.44 23.625 ;
     RECT  2.16 23.895 19.44 24.165 ;
     RECT  2.16 24.435 19.44 24.705 ;
     RECT  2.16 24.975 19.44 25.245 ;
     RECT  2.16 25.515 19.44 25.785 ;
     RECT  2.16 26.055 19.44 26.325 ;
     RECT  2.16 26.595 19.44 26.865 ;
     RECT  2.16 27.135 19.44 27.405 ;
     RECT  2.16 27.675 19.44 27.945 ;
     RECT  2.16 28.215 19.44 28.485 ;
     RECT  2.16 28.755 19.44 29.025 ;
     RECT  2.16 29.295 19.44 29.565 ;
     RECT  2.16 29.835 19.44 30.105 ;
     RECT  2.16 30.375 19.44 30.645 ;
     RECT  2.16 30.915 19.44 31.185 ;
     RECT  2.16 31.455 19.44 31.725 ;
     RECT  2.16 31.995 19.44 32.265 ;
     RECT  2.16 32.535 19.44 32.805 ;
     RECT  2.16 33.075 19.44 33.345 ;
     RECT  2.16 33.615 19.44 33.885 ;
     RECT  2.16 34.155 19.44 34.425 ;
     RECT  2.16 34.695 19.44 34.965 ;
     RECT  2.16 35.235 19.44 35.505 ;
     RECT  2.16 35.775 19.44 36.045 ;
     RECT  2.16 36.315 19.44 36.585 ;
     RECT  2.16 36.855 19.44 37.125 ;
     RECT  2.16 37.395 19.44 37.665 ;
     RECT  2.16 37.935 19.44 38.205 ;
     RECT  2.16 38.475 19.44 38.745 ;
     RECT  2.16 39.015 19.44 39.285 ;
     RECT  2.16 39.555 19.44 39.825 ;
     RECT  2.16 40.095 19.44 40.365 ;
     RECT  2.16 40.635 19.44 40.905 ;
     RECT  2.16 41.175 19.44 41.445 ;
     RECT  2.16 41.715 19.44 41.985 ;
     RECT  2.16 42.255 19.44 42.525 ;
     RECT  2.16 42.795 19.44 43.065 ;
     RECT  2.16 43.335 19.44 43.605 ;
     RECT  2.16 43.875 19.44 44.145 ;
     RECT  2.16 44.415 19.44 44.685 ;
     RECT  2.16 44.955 19.44 45.225 ;
    LAYER M1 ;
     RECT  2.16 2.151 19.44 45.369 ;
    LAYER M2 ;
     RECT  0.103 38.214 0.203 38.232 ;
     RECT  0.463 28.422 0.499 28.44 ;
     RECT  0.463 43.308 0.499 43.326 ;
     RECT  0.499 27.846 0.535 28.44 ;
     RECT  0.103 31.536 0.535 31.554 ;
     RECT  0.103 40.176 0.535 40.194 ;
     RECT  0.499 42.606 0.535 43.326 ;
     RECT  0.103 5.616 2.155 5.634 ;
     RECT  0.103 4.626 2.16 4.644 ;
     RECT  2.155 5.472 2.16 5.634 ;
     RECT  0.535 19.278 2.16 19.296 ;
     RECT  0.103 20.736 2.16 20.754 ;
     RECT  0.103 23.022 2.16 23.04 ;
     RECT  0.535 25.866 2.16 25.884 ;
     RECT  0.535 27.342 2.16 28.476 ;
     RECT  0.535 29.61 2.16 30.168 ;
     RECT  0.535 31.23 2.16 31.554 ;
     RECT  0.535 32.472 2.16 34.758 ;
     RECT  0.103 36.126 2.16 36.144 ;
     RECT  0.535 37.602 2.16 37.62 ;
     RECT  2.047 38.484 2.16 38.502 ;
     RECT  0.535 39.87 2.16 40.194 ;
     RECT  0.535 42.03 2.16 44.37 ;
     RECT  2.16 2.151 2.875 45.369 ;
     RECT  2.875 2.151 4.415 45.486 ;
     RECT  4.415 2.151 4.819 45.414 ;
     RECT  4.819 1.998 5.251 45.414 ;
     RECT  5.251 1.881 5.683 45.45 ;
     RECT  5.683 1.881 6.547 45.486 ;
     RECT  6.547 1.881 8.303 45.558 ;
     RECT  8.303 1.881 14.783 45.45 ;
     RECT  14.783 1.881 14.827 45.369 ;
     RECT  14.827 1.836 17.915 45.369 ;
     RECT  17.915 1.881 19.103 45.369 ;
     RECT  19.103 1.926 19.44 45.369 ;
     RECT  19.44 9.126 19.679 31.104 ;
     RECT  19.44 32.976 19.679 32.994 ;
     RECT  19.44 1.926 19.895 5.454 ;
     RECT  19.895 1.962 19.931 5.454 ;
     RECT  19.679 9.126 19.931 29.214 ;
     RECT  19.44 33.786 19.931 35.532 ;
     RECT  19.44 39.294 19.931 39.312 ;
     RECT  19.931 9.126 19.967 14.508 ;
     RECT  19.679 30.006 19.967 31.104 ;
     RECT  19.931 33.786 19.967 35.46 ;
     RECT  19.967 34.128 20.003 34.758 ;
     RECT  20.003 34.362 20.039 34.758 ;
     RECT  19.931 15.462 20.111 23.544 ;
     RECT  19.931 24.336 20.147 29.214 ;
     RECT  20.111 19.242 20.183 23.544 ;
     RECT  19.967 9.126 20.255 9.504 ;
     RECT  20.183 19.242 20.399 21.384 ;
     RECT  19.931 4.896 20.471 5.364 ;
     RECT  20.111 15.462 20.471 18.414 ;
     RECT  19.931 1.962 20.507 3.834 ;
     RECT  20.471 4.896 20.507 4.914 ;
     RECT  19.967 11.016 20.507 14.508 ;
     RECT  20.471 15.462 20.507 16.938 ;
     RECT  20.471 18.036 20.507 18.414 ;
     RECT  20.147 24.336 20.507 29.052 ;
     RECT  20.507 11.016 20.543 11.664 ;
     RECT  20.183 22.284 20.543 23.544 ;
     RECT  19.967 30.006 20.615 30.87 ;
     RECT  20.543 22.284 20.867 22.338 ;
     RECT  20.507 24.336 20.939 25.119 ;
     RECT  20.543 23.166 20.975 23.544 ;
     RECT  20.975 23.436 21.011 23.544 ;
     RECT  20.615 30.006 21.011 30.294 ;
     RECT  20.507 18.036 21.083 18.144 ;
     RECT  20.867 22.284 21.119 22.302 ;
     RECT  21.083 18.036 21.155 18.054 ;
     RECT  20.507 16.506 21.191 16.938 ;
     RECT  21.191 16.848 21.227 16.938 ;
     RECT  20.399 19.386 21.263 21.384 ;
     RECT  20.507 13.986 21.271 14.508 ;
     RECT  20.507 15.462 21.271 15.48 ;
     RECT  21.263 19.386 21.271 19.944 ;
     RECT  20.255 9.486 21.307 9.504 ;
     RECT  21.227 16.884 21.335 16.938 ;
     RECT  20.507 12.636 21.343 12.654 ;
     RECT  21.271 19.08 21.371 19.944 ;
     RECT  21.263 21.096 21.371 21.384 ;
     RECT  21.343 40.536 21.379 40.554 ;
     RECT  21.307 9.126 21.415 9.504 ;
     RECT  20.507 1.962 21.443 3.474 ;
     RECT  21.271 13.986 21.443 15.48 ;
     RECT  21.443 2.88 21.479 3.474 ;
     RECT  20.939 24.372 21.479 25.119 ;
     RECT  21.379 40.536 21.479 40.968 ;
     RECT  21.011 30.186 21.487 30.294 ;
     RECT  21.443 1.962 21.515 1.98 ;
     RECT  21.479 2.916 21.515 3.474 ;
     RECT  21.379 7.704 21.515 7.722 ;
     RECT  21.343 12.456 21.515 12.654 ;
     RECT  21.443 13.986 21.515 14.67 ;
     RECT  21.443 15.462 21.515 15.48 ;
     RECT  21.335 16.884 21.515 16.902 ;
     RECT  21.371 19.62 21.515 19.944 ;
     RECT  21.011 23.526 21.515 23.544 ;
     RECT  21.479 24.372 21.515 25.074 ;
     RECT  20.507 26.064 21.515 26.082 ;
     RECT  20.507 27.216 21.515 27.774 ;
     RECT  20.507 28.8 21.515 29.052 ;
     RECT  21.487 30.186 21.515 30.87 ;
     RECT  20.039 34.74 21.515 34.758 ;
     RECT  21.415 9.09 21.551 9.504 ;
     RECT  21.515 14.571 21.551 14.67 ;
     RECT  21.371 21.096 21.551 21.258 ;
     RECT  21.515 27.612 21.551 27.63 ;
     RECT  21.551 9.486 21.587 9.504 ;
     RECT  21.551 21.096 21.587 21.186 ;
     RECT  21.515 30.726 21.587 30.87 ;
     RECT  21.479 40.95 21.587 40.968 ;
    LAYER M3 ;
     RECT  20.484 0.715 20.502 1.003 ;
     RECT  21.456 0.859 21.474 1.723 ;
     RECT  19.908 1.003 20.502 1.867 ;
     RECT  14.832 1.831 14.85 1.876 ;
     RECT  18.72 1.579 18.738 1.876 ;
     RECT  17.892 1.831 17.91 1.921 ;
     RECT  18.72 1.876 19.098 1.921 ;
     RECT  21.456 1.723 21.51 1.985 ;
     RECT  5.256 1.876 5.274 1.993 ;
     RECT  15.66 1.876 15.678 1.993 ;
     RECT  21.456 1.985 21.474 2.011 ;
     RECT  13.536 1.921 13.554 2.101 ;
     RECT  15.66 1.993 15.786 2.101 ;
     RECT  8.136 1.723 8.154 2.143 ;
     RECT  13.464 2.101 13.554 2.143 ;
     RECT  12.168 1.957 12.186 2.219 ;
     RECT  14.832 1.876 14.922 2.227 ;
     RECT  17.892 1.921 19.098 2.255 ;
     RECT  13.215 2.143 13.554 2.263 ;
     RECT  14.292 2.227 14.922 2.263 ;
     RECT  18.252 2.255 19.098 2.263 ;
     RECT  19.872 1.867 20.502 2.263 ;
     RECT  21.42 2.011 21.474 2.291 ;
     RECT  2.415 2.143 2.505 2.413 ;
     RECT  4.824 1.993 5.274 2.413 ;
     RECT  10.515 2.143 10.605 2.413 ;
     RECT  15.66 2.101 16.074 2.413 ;
     RECT  12.816 2.263 14.922 2.641 ;
     RECT  15.66 2.413 16.197 2.641 ;
     RECT  21.456 2.291 21.474 2.731 ;
     RECT  11.952 2.263 11.97 2.803 ;
     RECT  4.824 2.413 5.397 2.839 ;
     RECT  21.456 2.731 21.51 2.903 ;
     RECT  12.816 2.641 16.197 2.911 ;
     RECT  12.816 2.911 16.722 2.939 ;
     RECT  6.768 2.911 6.786 3.001 ;
     RECT  15.84 2.939 16.722 3.037 ;
     RECT  6.768 3.001 6.858 3.101 ;
     RECT  7.815 2.143 8.154 3.173 ;
     RECT  15.84 3.037 16.794 3.299 ;
     RECT  21.492 2.903 21.51 3.479 ;
     RECT  18.252 2.263 20.502 3.577 ;
     RECT  12.816 2.939 14.85 3.685 ;
     RECT  18.144 3.577 20.502 3.713 ;
     RECT  10.515 2.413 10.797 3.847 ;
     RECT  4.824 2.839 5.49 3.991 ;
     RECT  6.552 3.181 6.714 3.991 ;
     RECT  2.415 2.413 2.697 4.171 ;
     RECT  7.815 3.173 8.097 4.261 ;
     RECT  2.304 4.171 2.697 4.315 ;
     RECT  11.664 2.803 11.97 4.423 ;
     RECT  12.816 3.685 14.994 4.423 ;
     RECT  4.824 3.991 6.714 4.459 ;
     RECT  4.536 4.459 6.714 4.495 ;
     RECT  18.288 3.713 20.502 4.495 ;
     RECT  4.464 4.495 6.714 4.531 ;
     RECT  18.252 4.495 20.502 4.541 ;
     RECT  2.268 4.315 2.697 4.621 ;
     RECT  10.476 3.847 10.797 4.621 ;
     RECT  0.108 4.603 0.126 4.649 ;
     RECT  3.996 4.531 6.714 4.765 ;
     RECT  7.776 4.261 8.097 4.765 ;
     RECT  3.996 4.765 8.097 4.829 ;
     RECT  2.268 4.621 3.078 4.891 ;
     RECT  18.288 4.541 20.502 4.919 ;
     RECT  17.46 4.729 17.478 4.999 ;
     RECT  2.232 4.891 3.078 5.071 ;
     RECT  4.32 4.829 8.097 5.071 ;
     RECT  11.664 4.423 14.994 5.197 ;
     RECT  15.84 3.299 16.197 5.197 ;
     RECT  2.232 5.071 3.51 5.213 ;
     RECT  11.664 5.197 16.197 5.269 ;
     RECT  11.664 5.269 16.29 5.305 ;
     RECT  2.232 5.213 2.862 5.323 ;
     RECT  4.32 5.071 8.298 5.341 ;
     RECT  17.388 4.999 17.478 5.341 ;
     RECT  18.54 4.919 20.466 5.369 ;
     RECT  4.32 5.341 9.018 5.431 ;
     RECT  21.456 5.323 21.474 5.467 ;
     RECT  2.16 5.323 2.862 5.495 ;
     RECT  18.54 5.369 20.322 5.504 ;
     RECT  10.476 4.621 10.926 5.575 ;
     RECT  4.32 5.431 9.198 5.611 ;
     RECT  0.108 5.611 0.126 5.648 ;
     RECT  3.996 5.611 9.198 5.693 ;
     RECT  2.304 5.495 2.862 5.765 ;
     RECT  7.452 5.693 9.198 5.765 ;
     RECT  9.936 5.575 10.926 5.881 ;
     RECT  2.304 5.765 2.79 6.179 ;
     RECT  18.576 5.504 20.322 6.619 ;
     RECT  3.996 5.693 6.714 6.691 ;
     RECT  7.452 5.765 8.838 6.691 ;
     RECT  17.1 5.341 17.478 6.781 ;
     RECT  18.36 6.619 20.322 6.781 ;
     RECT  0.144 6.667 0.162 6.797 ;
     RECT  3.96 6.691 8.838 6.961 ;
     RECT  11.664 5.305 16.362 7.087 ;
     RECT  17.1 6.781 20.322 7.087 ;
     RECT  2.304 6.179 2.697 7.189 ;
     RECT  3.456 6.961 8.838 7.189 ;
     RECT  2.304 7.189 8.838 7.229 ;
     RECT  3.528 7.229 8.838 7.357 ;
     RECT  9.684 5.881 10.926 7.357 ;
     RECT  21.42 5.467 21.474 7.483 ;
     RECT  21.384 7.483 21.474 7.627 ;
     RECT  21.384 7.627 21.51 7.771 ;
     RECT  21.312 7.771 21.51 7.997 ;
     RECT  2.304 7.229 2.79 8.041 ;
     RECT  3.528 7.357 10.926 8.041 ;
     RECT  0.144 8.059 0.162 8.189 ;
     RECT  2.304 8.041 10.926 8.311 ;
     RECT  11.664 7.087 20.322 8.311 ;
     RECT  2.304 8.311 20.322 8.429 ;
     RECT  21.348 7.997 21.51 9.085 ;
     RECT  21.348 9.085 21.546 9.121 ;
     RECT  2.304 8.429 2.754 9.211 ;
     RECT  3.528 8.429 20.322 9.211 ;
     RECT  2.304 9.211 20.322 9.275 ;
     RECT  21.312 9.121 21.546 9.481 ;
     RECT  2.304 9.275 3.582 10.123 ;
     RECT  4.356 9.275 20.322 10.201 ;
     RECT  2.268 10.123 3.582 10.253 ;
     RECT  2.304 10.253 3.582 10.327 ;
     RECT  4.32 10.201 20.322 10.327 ;
     RECT  21.312 9.481 21.582 10.363 ;
     RECT  2.304 10.327 20.322 10.625 ;
     RECT  0.144 10.699 0.162 10.829 ;
     RECT  2.34 10.625 20.322 10.939 ;
     RECT  2.34 10.939 20.502 11.011 ;
     RECT  2.34 11.011 20.538 11.371 ;
     RECT  2.304 11.371 20.538 11.435 ;
     RECT  3.42 11.435 20.538 11.693 ;
     RECT  3.42 11.693 20.502 12.083 ;
     RECT  2.304 11.435 2.697 12.217 ;
     RECT  3.42 12.083 20.466 12.217 ;
     RECT  2.304 12.217 20.466 12.811 ;
     RECT  0.144 13.243 0.162 13.373 ;
     RECT  2.304 12.811 20.502 13.433 ;
     RECT  3.564 13.433 20.502 14.144 ;
     RECT  2.304 13.433 2.826 14.251 ;
     RECT  3.564 14.144 20.322 14.251 ;
     RECT  21.276 10.363 21.582 15.089 ;
     RECT  2.304 14.251 20.322 15.403 ;
     RECT  0.144 14.827 0.162 15.533 ;
     RECT  0.144 16.315 0.162 16.445 ;
     RECT  2.304 15.403 20.502 16.501 ;
     RECT  21.348 15.089 21.582 16.501 ;
     RECT  0.144 17.179 0.162 17.549 ;
     RECT  0.54 19.273 0.558 19.469 ;
     RECT  2.304 16.501 21.582 20.011 ;
     RECT  2.268 20.011 21.582 20.141 ;
     RECT  0.108 20.731 0.126 20.768 ;
     RECT  2.304 20.141 21.582 21.299 ;
     RECT  2.304 21.299 2.826 22.081 ;
     RECT  3.564 21.299 21.582 22.081 ;
     RECT  2.304 22.081 21.582 22.739 ;
     RECT  0.108 22.891 0.126 23.045 ;
     RECT  2.304 22.739 2.79 23.701 ;
     RECT  3.564 22.739 21.582 23.701 ;
     RECT  0.144 23.947 0.162 24.077 ;
     RECT  2.304 23.701 21.582 25.085 ;
     RECT  2.376 25.085 21.582 25.205 ;
     RECT  0.144 25.339 0.162 25.861 ;
     RECT  2.376 25.205 2.79 25.963 ;
     RECT  3.528 25.205 21.582 25.963 ;
     RECT  2.304 25.963 21.582 26.015 ;
     RECT  0.144 25.861 0.558 26.237 ;
     RECT  0.144 26.237 0.162 26.621 ;
     RECT  2.376 26.015 21.582 26.779 ;
     RECT  2.304 26.779 21.582 27.821 ;
     RECT  0.54 27.337 0.558 27.841 ;
     RECT  2.376 27.821 21.582 27.869 ;
     RECT  0.504 27.841 0.558 28.417 ;
     RECT  0.468 28.417 0.558 28.541 ;
     RECT  0.468 28.541 0.486 28.685 ;
     RECT  2.376 27.869 2.826 28.921 ;
     RECT  3.564 27.869 21.582 28.921 ;
     RECT  2.376 28.921 21.582 29.083 ;
     RECT  2.304 29.083 21.582 29.255 ;
     RECT  0.54 29.605 0.558 30.269 ;
     RECT  2.376 29.255 21.582 30.811 ;
     RECT  2.304 30.811 21.582 31.415 ;
     RECT  0.54 31.225 0.558 31.421 ;
     RECT  0.108 31.531 0.162 31.568 ;
     RECT  0.144 31.568 0.162 31.853 ;
     RECT  2.415 31.415 21.582 32.305 ;
     RECT  2.304 32.305 21.582 32.611 ;
     RECT  2.268 32.611 21.582 32.717 ;
     RECT  2.304 32.717 21.582 33.449 ;
     RECT  2.412 33.449 21.582 33.581 ;
     RECT  2.412 33.581 20.502 33.725 ;
     RECT  0.54 32.467 0.558 33.979 ;
     RECT  2.412 33.725 20.394 34.603 ;
     RECT  2.304 34.603 20.394 34.655 ;
     RECT  0.144 33.979 0.558 34.877 ;
     RECT  2.34 34.655 20.394 35.195 ;
     RECT  0.144 34.877 0.162 35.261 ;
     RECT  2.34 35.195 2.898 35.419 ;
     RECT  2.304 35.419 2.898 35.609 ;
     RECT  2.415 35.609 2.898 35.735 ;
     RECT  3.636 35.195 20.394 35.885 ;
     RECT  3.636 35.885 20.358 35.969 ;
     RECT  2.415 35.735 2.79 36.041 ;
     RECT  0.108 36.121 0.126 36.173 ;
     RECT  21.24 33.581 21.582 36.173 ;
     RECT  2.415 36.041 2.697 36.571 ;
     RECT  2.304 36.571 2.697 36.931 ;
     RECT  3.636 35.969 8.55 36.931 ;
     RECT  2.304 36.931 8.55 37.328 ;
     RECT  0.54 37.597 0.558 37.757 ;
     RECT  0.18 37.963 0.198 38.011 ;
     RECT  0.108 38.011 0.198 38.252 ;
     RECT  2.415 37.328 8.55 38.299 ;
     RECT  2.052 38.299 8.55 38.507 ;
     RECT  2.304 38.507 8.55 38.705 ;
     RECT  0.144 38.252 0.198 38.923 ;
     RECT  2.304 38.705 2.862 39.011 ;
     RECT  0.144 38.923 0.234 39.053 ;
     RECT  0.144 39.053 0.162 39.293 ;
     RECT  21.276 36.173 21.582 39.485 ;
     RECT  2.304 39.011 2.826 39.515 ;
     RECT  9.288 35.969 20.358 39.749 ;
     RECT  2.415 39.515 2.826 39.829 ;
     RECT  3.636 38.705 8.55 39.829 ;
     RECT  0.54 39.865 0.558 39.917 ;
     RECT  2.415 39.829 8.55 40.019 ;
     RECT  9.468 39.749 20.358 40.205 ;
     RECT  0.108 40.171 0.126 40.208 ;
     RECT  2.415 40.019 8.514 40.289 ;
     RECT  2.415 40.289 2.826 40.459 ;
     RECT  9.468 40.205 18.897 40.637 ;
     RECT  9.576 40.637 17.406 40.829 ;
     RECT  10.044 40.829 17.406 40.925 ;
     RECT  21.348 39.485 21.582 40.973 ;
     RECT  2.304 40.459 2.826 41.083 ;
     RECT  3.636 40.289 8.514 41.083 ;
     RECT  18.432 40.637 18.897 41.165 ;
     RECT  19.656 40.205 20.358 41.645 ;
     RECT  10.404 40.925 17.406 41.819 ;
     RECT  2.304 41.083 8.514 41.909 ;
     RECT  0.144 41.947 0.162 42.025 ;
     RECT  0.144 42.025 0.558 42.077 ;
     RECT  21.348 40.973 21.438 42.077 ;
     RECT  2.304 41.909 8.298 42.089 ;
     RECT  19.764 41.645 20.358 42.221 ;
     RECT  2.304 42.089 2.79 42.365 ;
     RECT  20.34 42.221 20.358 42.365 ;
     RECT  9.144 42.331 9.378 42.449 ;
     RECT  9.144 42.449 9.162 42.593 ;
     RECT  11.952 41.819 17.406 42.719 ;
     RECT  21.348 42.077 21.402 42.763 ;
     RECT  21.276 42.763 21.402 42.797 ;
     RECT  3.636 42.089 8.298 42.899 ;
     RECT  21.276 42.797 21.366 42.941 ;
     RECT  2.415 42.365 2.79 43.033 ;
     RECT  3.636 42.899 7.002 43.033 ;
     RECT  0.504 42.077 0.558 43.099 ;
     RECT  21.348 42.941 21.366 43.229 ;
     RECT  7.815 42.899 8.298 43.231 ;
     RECT  2.415 43.033 7.002 43.331 ;
     RECT  12.24 42.719 17.406 43.367 ;
     RECT  12.24 43.367 13.95 43.529 ;
     RECT  18.615 41.165 18.897 43.609 ;
     RECT  12.24 43.529 13.842 43.799 ;
     RECT  3.924 43.331 7.002 43.879 ;
     RECT  7.815 43.231 8.658 43.879 ;
     RECT  0.144 43.099 0.558 43.901 ;
     RECT  3.924 43.879 8.658 43.951 ;
     RECT  10.404 41.819 11.178 44.041 ;
     RECT  3.924 43.951 9.522 44.069 ;
     RECT  2.415 43.331 2.826 44.185 ;
     RECT  2.304 44.185 2.826 44.221 ;
     RECT  2.304 44.221 3.15 44.299 ;
     RECT  3.924 44.069 9.45 44.299 ;
     RECT  10.368 44.041 11.178 44.311 ;
     RECT  12.24 43.799 13.497 44.311 ;
     RECT  10.368 44.311 13.497 44.339 ;
     RECT  14.76 43.367 17.406 44.339 ;
     RECT  10.368 44.339 12.258 44.443 ;
     RECT  15.012 44.339 17.406 44.443 ;
     RECT  18.432 43.609 18.897 44.443 ;
     RECT  10.188 44.443 12.258 44.483 ;
     RECT  11.628 44.483 12.258 44.609 ;
     RECT  15.012 44.443 18.897 44.609 ;
     RECT  0.54 43.901 0.558 44.669 ;
     RECT  15.012 44.609 16.197 44.681 ;
     RECT  13.215 44.339 13.497 44.761 ;
     RECT  2.304 44.299 9.45 44.879 ;
     RECT  15.915 44.681 16.197 45.107 ;
     RECT  18.615 44.609 18.897 45.107 ;
     RECT  9.108 44.879 9.45 45.149 ;
     RECT  15.012 44.681 15.03 45.149 ;
     RECT  16.956 44.609 16.974 45.149 ;
     RECT  11.628 44.609 11.646 45.185 ;
     RECT  10.404 44.483 10.797 45.197 ;
     RECT  2.304 44.879 8.298 45.293 ;
     RECT  13.215 44.761 13.698 45.293 ;
     RECT  10.515 45.197 10.797 45.301 ;
     RECT  3.96 45.293 8.298 45.377 ;
     RECT  10.515 45.301 11.034 45.377 ;
     RECT  13.215 45.293 13.305 45.377 ;
     RECT  15.915 45.107 16.005 45.377 ;
     RECT  18.615 45.107 18.705 45.377 ;
     RECT  0.144 45.259 0.162 45.389 ;
     RECT  9.108 45.149 9.126 45.419 ;
     RECT  14.76 45.301 14.778 45.455 ;
     RECT  2.304 45.293 2.898 45.491 ;
     RECT  3.96 45.377 7.218 45.491 ;
     RECT  6.336 45.491 6.642 45.533 ;
     RECT  6.336 45.533 6.57 45.563 ;
     RECT  8.28 45.377 8.298 45.563 ;
     RECT  10.872 45.377 11.034 45.581 ;
     RECT  3.96 45.491 3.978 45.965 ;
     RECT  5.076 45.491 5.562 46.109 ;
     RECT  2.304 45.491 2.862 46.253 ;
     RECT  2.304 46.253 2.322 46.397 ;
     RECT  5.544 46.109 5.562 46.541 ;
     RECT  6.336 45.563 6.354 46.685 ;
     RECT  11.016 45.581 11.034 46.747 ;
     RECT  10.908 46.747 11.034 47.501 ;
    LAYER M4 ;
     RECT  0.06 4.176 2.408 46.68 ;
     RECT  2.408 2.148 2.512 46.68 ;
     RECT  2.512 2.418 2.704 46.68 ;
     RECT  2.704 4.464 5.105 46.68 ;
     RECT  5.105 4.464 5.108 45.528 ;
     RECT  5.108 2.148 5.212 45.528 ;
     RECT  5.212 2.418 5.404 45.528 ;
     RECT  5.404 6.528 5.573 19.08 ;
     RECT  5.404 25.92 5.573 39.192 ;
     RECT  5.105 46.512 5.573 46.68 ;
     RECT  5.404 20.16 5.717 24.936 ;
     RECT  5.404 40.32 5.717 40.488 ;
     RECT  5.404 41.472 5.717 45.528 ;
     RECT  5.717 21.072 5.74 24.216 ;
     RECT  5.573 7.776 5.747 19.08 ;
     RECT  5.747 9.216 5.788 19.08 ;
     RECT  5.573 25.92 5.861 36.216 ;
     RECT  5.573 37.44 5.939 39.192 ;
     RECT  5.788 9.312 5.969 19.08 ;
     RECT  5.861 25.92 5.969 34.968 ;
     RECT  5.969 11.328 5.987 19.08 ;
     RECT  5.939 37.44 6.005 37.608 ;
     RECT  5.969 30.672 6.131 34.968 ;
     RECT  6.131 31.104 6.221 34.968 ;
     RECT  5.404 5.184 6.275 5.208 ;
     RECT  5.987 11.328 6.323 14.232 ;
     RECT  5.717 41.76 6.329 45.528 ;
     RECT  6.323 11.328 6.364 11.352 ;
     RECT  5.573 46.656 6.365 46.68 ;
     RECT  5.74 23.376 6.401 24.216 ;
     RECT  6.221 31.296 6.401 34.968 ;
     RECT  5.573 6.528 6.437 6.552 ;
     RECT  6.401 33.312 6.515 34.968 ;
     RECT  5.939 38.688 6.515 39.192 ;
     RECT  6.401 31.296 6.545 32.184 ;
     RECT  6.515 38.784 6.545 39.192 ;
     RECT  5.747 7.776 6.577 7.8 ;
     RECT  6.329 42.672 6.653 45.528 ;
     RECT  5.987 15.36 6.685 19.08 ;
     RECT  5.74 21.072 6.689 22.008 ;
     RECT  6.545 39.072 6.755 39.192 ;
     RECT  6.401 23.424 6.757 24.216 ;
     RECT  5.969 25.92 6.757 29.208 ;
     RECT  6.757 23.424 6.761 29.208 ;
     RECT  6.005 37.584 6.761 37.608 ;
     RECT  6.755 39.168 6.761 39.192 ;
     RECT  5.861 36.192 6.797 36.216 ;
     RECT  6.689 21.504 6.829 22.008 ;
     RECT  6.577 7.344 7.045 7.8 ;
     RECT  6.685 15.36 7.045 19.368 ;
     RECT  6.515 33.84 7.045 34.968 ;
     RECT  5.717 40.464 7.261 40.488 ;
     RECT  6.323 12.528 7.369 14.232 ;
     RECT  6.653 42.672 7.369 45.192 ;
     RECT  7.081 5.664 7.808 5.688 ;
     RECT  7.045 7.344 7.808 7.992 ;
     RECT  5.969 9.312 7.808 10.344 ;
     RECT  7.369 12.48 7.808 14.232 ;
     RECT  7.045 15.36 7.808 20.328 ;
     RECT  6.829 21.504 7.808 22.344 ;
     RECT  6.761 23.424 7.808 27.96 ;
     RECT  6.761 28.944 7.808 29.208 ;
     RECT  6.545 31.296 7.808 31.896 ;
     RECT  7.045 33.84 7.808 35.016 ;
     RECT  7.261 39.744 7.808 40.488 ;
     RECT  7.369 42.192 7.808 45.192 ;
     RECT  7.808 2.148 7.912 45.372 ;
     RECT  7.621 0.096 7.955 0.12 ;
     RECT  7.912 2.148 8.053 45.192 ;
     RECT  8.053 1.728 8.104 45.192 ;
     RECT  8.104 1.728 8.165 1.752 ;
     RECT  8.104 25.728 8.237 25.752 ;
     RECT  8.104 39.744 8.273 39.768 ;
     RECT  8.104 19.344 8.345 20.328 ;
     RECT  8.345 20.304 8.381 20.328 ;
     RECT  8.104 21.696 8.381 21.72 ;
     RECT  8.104 12.768 8.453 12.792 ;
     RECT  9.421 29.088 9.505 29.112 ;
     RECT  9.529 26.736 9.709 26.76 ;
     RECT  9.709 26.736 9.745 26.904 ;
     RECT  9.445 6.912 9.817 6.936 ;
     RECT  8.104 9.36 9.853 9.384 ;
     RECT  9.817 6.912 9.889 7.656 ;
     RECT  9.853 8.784 9.889 9.384 ;
     RECT  9.889 6.912 9.961 9.384 ;
     RECT  9.457 40.608 10.033 40.632 ;
     RECT  8.104 5.472 10.141 5.496 ;
     RECT  10.141 5.472 10.177 5.784 ;
     RECT  9.961 6.912 10.177 9.816 ;
     RECT  10.177 5.472 10.508 9.816 ;
     RECT  10.105 10.848 10.508 10.872 ;
     RECT  9.637 21.984 10.508 22.008 ;
     RECT  9.529 25.152 10.508 25.176 ;
     RECT  9.745 26.736 10.508 27.48 ;
     RECT  9.961 30.816 10.508 30.84 ;
     RECT  10.249 34.128 10.508 34.152 ;
     RECT  10.033 40.608 10.508 40.92 ;
     RECT  8.104 44.448 10.508 45.192 ;
     RECT  10.508 2.148 10.612 45.372 ;
     RECT  10.612 2.418 10.804 45.372 ;
     RECT  10.804 28.992 10.829 29.016 ;
     RECT  10.853 46.752 10.937 46.776 ;
     RECT  10.861 45.552 10.945 45.576 ;
     RECT  10.804 15.984 11.369 16.008 ;
     RECT  10.804 37.872 12.049 37.896 ;
     RECT  12.049 37.152 12.301 37.896 ;
     RECT  10.804 39.024 12.301 40.92 ;
     RECT  12.301 37.152 12.373 40.92 ;
     RECT  12.373 36.624 12.877 40.92 ;
     RECT  10.804 41.904 12.877 41.928 ;
     RECT  12.877 36.624 13.021 41.928 ;
     RECT  10.804 5.472 13.208 9.816 ;
     RECT  12.157 12.528 13.208 12.552 ;
     RECT  13.057 19.008 13.208 19.032 ;
     RECT  10.804 21.792 13.208 21.816 ;
     RECT  13.165 26.784 13.208 26.808 ;
     RECT  10.804 32.256 13.208 32.328 ;
     RECT  10.804 34.128 13.208 34.152 ;
     RECT  13.021 36.624 13.208 42.504 ;
     RECT  13.208 2.148 13.312 45.372 ;
     RECT  13.312 2.418 13.504 45.102 ;
     RECT  13.504 26.784 13.565 26.808 ;
     RECT  13.504 33.84 14.713 34.152 ;
     RECT  14.713 33.408 14.821 34.152 ;
     RECT  13.504 35.568 14.821 42.504 ;
     RECT  14.821 30.768 14.893 30.792 ;
     RECT  14.893 30.672 14.933 30.792 ;
     RECT  14.821 33.312 14.933 42.504 ;
     RECT  14.933 35.472 15.073 42.504 ;
     RECT  13.504 19.008 15.361 19.032 ;
     RECT  13.504 5.472 15.908 9.816 ;
     RECT  15.001 14.832 15.908 14.856 ;
     RECT  15.361 19.008 15.908 19.32 ;
     RECT  13.504 21.744 15.908 21.816 ;
     RECT  15.001 22.8 15.908 22.824 ;
     RECT  14.965 26.784 15.908 26.808 ;
     RECT  15.793 29.328 15.908 29.352 ;
     RECT  14.933 30.672 15.908 30.696 ;
     RECT  13.504 32.256 15.908 32.328 ;
     RECT  14.933 33.312 15.908 34.152 ;
     RECT  15.073 35.472 15.908 43.08 ;
     RECT  15.908 2.148 16.012 45.372 ;
     RECT  16.012 2.418 16.204 45.102 ;
     RECT  16.204 26.784 16.373 26.808 ;
     RECT  16.204 19.008 17.269 19.608 ;
     RECT  17.269 19.008 17.485 19.656 ;
     RECT  16.204 20.88 17.485 22.488 ;
     RECT  16.204 24.912 17.665 24.936 ;
     RECT  16.204 5.472 17.893 9.816 ;
     RECT  17.485 19.008 17.953 22.488 ;
     RECT  16.204 23.664 17.953 23.688 ;
     RECT  17.893 4.512 17.989 9.816 ;
     RECT  17.665 14.4 18.133 14.424 ;
     RECT  18.133 14.4 18.205 14.856 ;
     RECT  17.665 24.864 18.205 24.936 ;
     RECT  16.204 30.672 18.241 31.128 ;
     RECT  18.205 14.4 18.277 14.952 ;
     RECT  17.917 13.104 18.457 13.128 ;
     RECT  18.277 14.4 18.457 15 ;
     RECT  18.205 24.864 18.493 25.464 ;
     RECT  18.205 11.52 18.565 11.544 ;
     RECT  18.457 13.104 18.565 15 ;
     RECT  18.241 2.88 18.608 2.904 ;
     RECT  17.989 4.512 18.608 10.104 ;
     RECT  18.565 11.52 18.608 15 ;
     RECT  17.593 16.848 18.608 16.872 ;
     RECT  17.953 19.008 18.608 23.688 ;
     RECT  18.493 24.864 18.608 26.04 ;
     RECT  17.629 27.072 18.608 27.096 ;
     RECT  16.204 29.328 18.608 29.352 ;
     RECT  18.241 30.432 18.608 31.128 ;
     RECT  16.204 32.256 18.608 34.152 ;
     RECT  16.204 35.472 18.608 43.08 ;
     RECT  17.881 44.448 18.608 44.472 ;
     RECT  18.608 2.148 18.709 45.372 ;
     RECT  18.709 1.584 18.712 45.372 ;
     RECT  18.712 1.584 18.904 45.102 ;
     RECT  18.904 1.584 19.897 10.248 ;
     RECT  18.904 11.232 19.897 43.368 ;
     RECT  19.897 1.008 20.243 43.368 ;
     RECT  20.243 1.008 20.473 43.08 ;
     RECT  20.473 0.72 21.337 43.08 ;
     RECT  21.337 0.72 21.564 43.224 ;
    LAYER M5 ;
     RECT  7.92 0.016 8.088 0.085 ;
     RECT  2.4 2.137 2.52 2.151 ;
     RECT  5.1 2.137 5.22 2.151 ;
     RECT  7.632 0.085 8.088 2.151 ;
     RECT  10.5 2.137 10.62 2.151 ;
     RECT  13.2 2.137 13.32 2.151 ;
     RECT  15.9 2.137 16.02 2.151 ;
     RECT  18.6 2.137 18.72 2.151 ;
     RECT  18.6 2.151 18.912 4.501 ;
     RECT  5.1 2.151 5.412 5.173 ;
     RECT  2.4 2.151 2.712 5.221 ;
     RECT  2.256 5.221 2.712 5.363 ;
     RECT  7.632 2.151 8.112 5.461 ;
     RECT  5.1 5.173 6.264 5.605 ;
     RECT  4.32 5.605 6.264 6.805 ;
     RECT  7.632 5.461 9.096 6.901 ;
     RECT  3.984 6.805 6.264 7.427 ;
     RECT  4.56 7.427 6.264 7.811 ;
     RECT  4.56 7.811 5.736 9.349 ;
     RECT  4.416 9.349 5.736 9.637 ;
     RECT  7.632 6.901 9.48 9.637 ;
     RECT  4.416 9.637 9.48 11.845 ;
     RECT  17.904 4.501 18.912 12.277 ;
     RECT  20.208 5.173 20.232 12.277 ;
     RECT  3.792 11.845 9.48 13.139 ;
     RECT  2.4 5.363 2.712 13.237 ;
     RECT  2.4 13.237 2.808 13.379 ;
     RECT  3.792 13.139 6.36 14.291 ;
     RECT  4.416 14.291 6.36 16.501 ;
     RECT  2.4 13.379 2.712 16.693 ;
     RECT  4.416 16.501 6.504 17.605 ;
     RECT  2.304 16.693 2.712 17.891 ;
     RECT  3.888 17.605 6.504 18.181 ;
     RECT  7.632 13.139 9.48 18.181 ;
     RECT  3.888 18.181 9.48 19.427 ;
     RECT  21.408 21.109 21.432 21.395 ;
     RECT  4.416 19.427 9.48 24.995 ;
     RECT  21.408 25.237 21.432 25.571 ;
     RECT  7.536 24.995 9.48 25.715 ;
     RECT  4.416 24.995 6.36 25.955 ;
     RECT  7.632 25.715 9.48 26.773 ;
     RECT  10.5 2.151 10.812 26.773 ;
     RECT  7.632 26.773 10.812 26.915 ;
     RECT  4.416 25.955 6.216 27.253 ;
     RECT  7.632 26.915 9.48 27.253 ;
     RECT  4.416 27.253 9.48 27.301 ;
     RECT  3.84 27.301 9.48 29.123 ;
     RECT  3.84 29.123 9.096 29.219 ;
     RECT  3.84 29.219 6.264 29.459 ;
     RECT  4.416 29.459 6.264 31.379 ;
     RECT  5.1 31.379 6.264 33.301 ;
     RECT  5.1 33.301 6.504 37.573 ;
     RECT  17.904 12.277 20.232 37.619 ;
     RECT  5.1 37.573 6.744 37.621 ;
     RECT  2.4 17.891 2.712 37.765 ;
     RECT  2.4 37.765 2.856 38.101 ;
     RECT  4.32 37.621 6.744 38.101 ;
     RECT  2.4 38.101 6.744 38.675 ;
     RECT  4.8 38.675 6.744 39.107 ;
     RECT  3.792 38.675 3.816 39.203 ;
     RECT  4.8 39.107 6.504 40.499 ;
     RECT  2.4 38.675 2.712 42.517 ;
     RECT  2.304 42.517 2.712 42.659 ;
     RECT  5.1 40.499 6.504 42.709 ;
     RECT  7.8 29.219 9.096 42.709 ;
     RECT  4.992 42.709 6.504 42.851 ;
     RECT  2.4 42.659 2.712 43.285 ;
     RECT  20.208 37.619 20.232 43.379 ;
     RECT  2.4 43.285 3.24 44.339 ;
     RECT  7.488 42.709 9.096 44.483 ;
     RECT  17.904 37.619 18.912 44.483 ;
     RECT  7.8 44.483 9.096 44.531 ;
     RECT  2.4 44.339 2.712 44.725 ;
     RECT  2.304 44.725 2.712 44.915 ;
     RECT  5.1 42.851 6.504 45.011 ;
     RECT  5.1 45.011 5.976 45.203 ;
     RECT  2.4 44.915 2.712 45.369 ;
     RECT  5.1 45.203 5.412 45.369 ;
     RECT  7.8 44.531 8.112 45.369 ;
     RECT  13.2 2.151 13.512 45.369 ;
     RECT  15.9 2.151 16.212 45.369 ;
     RECT  18.6 44.483 18.912 45.369 ;
     RECT  2.4 45.369 2.52 45.383 ;
     RECT  5.1 45.369 5.22 45.383 ;
     RECT  7.8 45.369 7.92 45.383 ;
     RECT  10.5 26.915 10.812 45.383 ;
     RECT  13.2 45.369 13.32 45.383 ;
     RECT  15.9 45.369 16.02 45.383 ;
     RECT  18.6 45.369 18.72 45.383 ;
     RECT  10.896 45.541 10.92 46.787 ;
  END
END qkd_rlysh0_296
END LIBRARY
